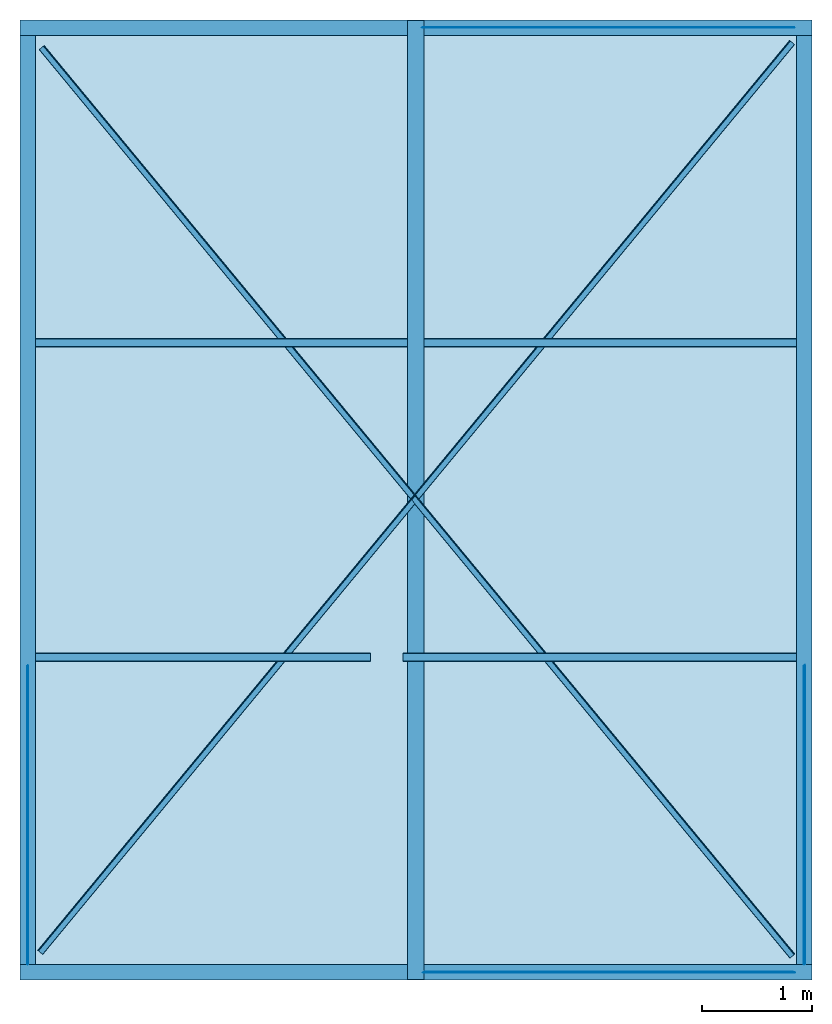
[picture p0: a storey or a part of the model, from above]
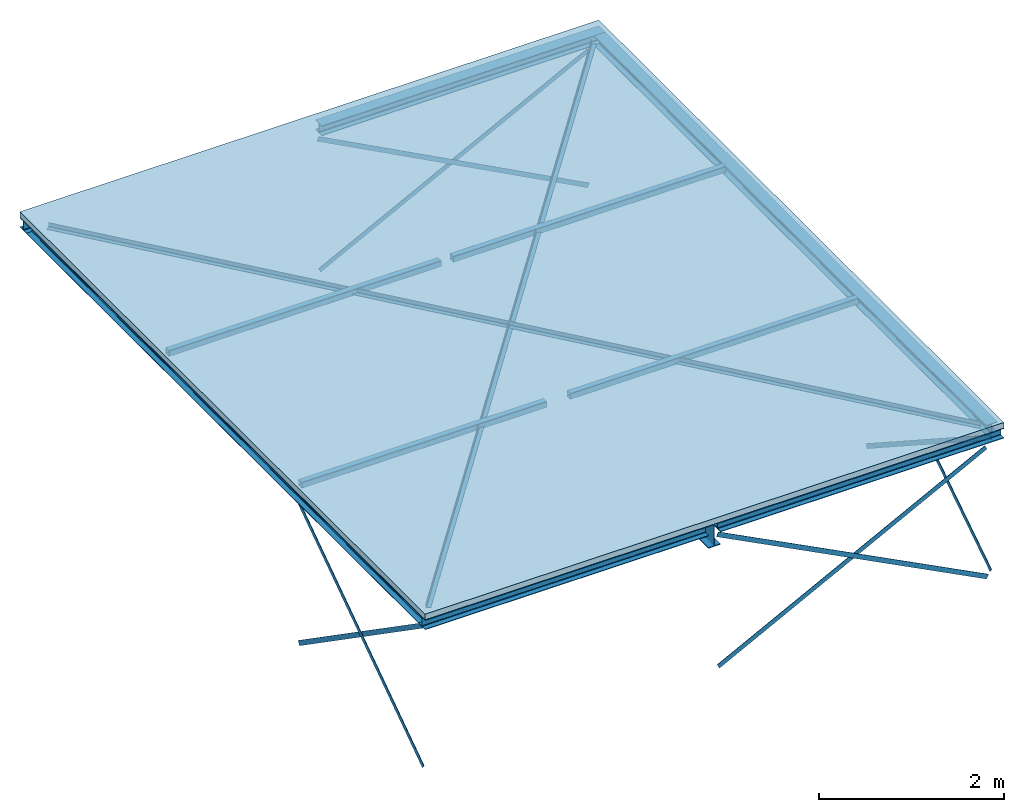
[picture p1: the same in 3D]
Properties of the parts of a building model (IFC2X3), part 1 of 2

# File
Description: ViewDefinition [CoordinationView_V2.0]
File name: 2021082
Time: 2022-08-02T08:48:02
Written by: The EXPRESS Data Manager Version 5.02.0100.07 : 28 Aug 2013
Made in: 22.0.2.392 - Exporter 22.0.2.392 - Alternate UI 22.0.2.392
Comment: STEP Physical File produced by: The EXPRESS Data Manager Version 5.02.0100.07 : 28 Aug 2013 * Module: EDMstepFileFactory/EDMstandAlone * Creation date: Tue Aug 02 08:48:02 2022 * Host: R2PC02 * Database: C:\Users\HANSVA~1\AppData\Local\Temp\1c85909f-41f3-4abc-839f-18ef85b8f30f\689eabe4-1559-4020-89f1-15476b5d3bc4\ifc * Database version: 5507 * Database creation date: Tue Aug 02 08:47:47 2022 * Schema: IFC2X3 * Model: DataRepository.ifc * Model creation date: Tue Aug 02 08:47:47 2022 * Header model: DataRepository.ifc_HeaderModel * Header model creation date: Tue Aug 02 08:47:47 2022 * EDMuser: sdai-user * EDMgroup: sdai-group * License ID and type: 5605 : Permanent license. Expiry date: * EDMstepFileFactory options: 020000

# IfcProject, 2021082
LongName: IKC Woensdrecht; Phase: Project Status

# IfcSite, Default
RefLatitude: 52, 22, 58, 797912; RefLongitude: 4, 54, 57, 599601; RefElevation: 0 mm
Pset_ProductRequirements - Category: Project Information

# IfcBuilding
Pset_BuildingCommon - NumberOfStoreys: 9
Pset_ProductRequirements - Category: Project Information

# IfcBuildingStorey: Level:A_hoogte_3.5mm (9)
Pset_ProductRequirements - Category: Levels
Name | LongName | Elevation (mm) | Pset_AirSideSystemInformation, Name = Pset_ProductRequirements, Name
-01 kelder | -01 kelder | -3500 | P.P.N
-00 fundatie | -00 fundatie | -1085 | -00 fundatie
00 begane grond | 00 begane grond | -2.70717e-13 | 00 begane grond
01 eerste verdieping | 01 eerste verdieping | 3500 | 01 eerste verdieping
02 tweede verdieping | 02 tweede verdieping | 7000 | 02 tweede verdieping
03 derde verdieping | 03 derde verdieping | 10500 | 03 derde verdieping
04 vierde verdieping | 04 vierde verdieping | 14000 | 04 vierde verdieping
05 vijfde verdieping | 05 vijfde verdieping | 17500 | 05 vijfde verdieping
06 zesde verdieping | 06 zesde verdieping | 21000 | 06 zesde verdieping

# IfcBeam: BERSnl_28_SF_LIB_balk hea -SH_gen_ISR:balk gen hea140 (7)
Type - PredefinedType: BEAM
Type - Pset_BeamCommon - IsExternal: no; LoadBearing: yes
Type - Pset_ProductRequirements - Category: Structural Framing
Type - Pset_ReinforcementBarPitchOfBeam - Description: HEA140
Classification: 28.10 hoofddraagconstructies; kolommen en liggers, algemeen (verzamelniveau) (Uniformat); Material: 00_Staal_generiek
Pset_BeamCommon - Slope: 0 deg; IsExternal: yes; Reference: balk gen hea140
Pset_PrecastConcreteElementGeneral - ElementWeight: 0 kg
Pset_QuantityTakeOff - Reference: balk gen hea140
Pset_ReinforcementBarPitchOfBeam - Reference: balk gen hea140
Name (BERSnl_28_SF_LIB_balk hea -SH_gen_ISR:balk gen hea140:...) | In | Span (mm)
849789 | 03 derde verdieping | 1500
851261 | 03 derde verdieping | 1000
851611 | 03 derde verdieping | 1500
852184 | 03 derde verdieping | 1920
855632 | 03 derde verdieping | 1500
855634 | 03 derde verdieping | 1500
966051 | 01 eerste verdieping | 3600

# IfcBeam: BERSnl_28_SF_LIB_balk hea -SH_gen_ISR:balk gen hea160 (9)
In: 01 eerste verdieping
Type - PredefinedType: BEAM
Type - Pset_BeamCommon - IsExternal: no; LoadBearing: yes
Type - Pset_ProductRequirements - Category: Structural Framing
Type - Pset_ReinforcementBarPitchOfBeam - Description: HEA160
Classification: 28.10 hoofddraagconstructies; kolommen en liggers, algemeen (verzamelniveau) (Uniformat); Material: 00_Staal_generiek
Pset_BeamCommon - IsExternal: yes; Reference: balk gen hea160
Pset_PrecastConcreteElementGeneral - ElementWeight: 0 kg
Pset_QuantityTakeOff - Reference: balk gen hea160
Pset_ReinforcementBarPitchOfBeam - Reference: balk gen hea160
Name (BERSnl_28_SF_LIB_balk hea -SH_gen_ISR:balk gen hea160:...) | Slope (deg) | Span (mm)
949146 | 0 | 2500
949247 | 0 | 2500
949938 | 0.963939 | 8916.3
953803 | 0 | 2500
953818 | 0 | 2500
954060 | 0 | 2500
954073 | 0 | 2500
959555 | 0 | 2500
959983 | 0 | 2500

# IfcBeam: BERSnl_28_SF_LIB_balk hea -SH_gen_ISR:balk gen hea180 (2)
In: 01 eerste verdieping
Type - PredefinedType: BEAM
Type - Pset_BeamCommon - IsExternal: no; LoadBearing: yes
Type - Pset_ProductRequirements - Category: Structural Framing
Type - Pset_ReinforcementBarPitchOfBeam - Description: HEA180
Classification: 28.10 hoofddraagconstructies; kolommen en liggers, algemeen (verzamelniveau) (Uniformat); Material: 00_Staal_generiek
Pset_BeamCommon - Slope: 0 deg; IsExternal: yes; Reference: balk gen hea180; Span: 1500 mm
Pset_PrecastConcreteElementGeneral - ElementWeight: 0 kg
Pset_QuantityTakeOff - Reference: balk gen hea180
Pset_ReinforcementBarPitchOfBeam - Reference: balk gen hea180
Name (BERSnl_28_SF_LIB_balk hea -SH_gen_ISR:balk gen hea180:...)
1052827
1053251

# IfcBeam: BERSnl_28_SF_LIB_balk hea -SH_gen_ISR:balk gen hea300 (2)
In: 02 tweede verdieping
Type - PredefinedType: BEAM
Type - Pset_BeamCommon - IsExternal: no; LoadBearing: yes; FireRating: 90
Type - Pset_ConcreteElementGeneral - FireRating: 90
Type - Pset_ProductRequirements - Category: Structural Framing
Type - Pset_ReinforcementBarPitchOfBeam - Description: HEA300
Classification: 28.10 hoofddraagconstructies; kolommen en liggers, algemeen (verzamelniveau) (Uniformat); Material: 00_Staal_generiek
Pset_BeamCommon - Slope: 0 deg; IsExternal: yes; Reference: balk gen hea300
Pset_PrecastConcreteElementGeneral - ElementWeight: 0 kg
Pset_QuantityTakeOff - Reference: balk gen hea300
Pset_ReinforcementBarPitchOfBeam - Reference: balk gen hea300
Name (BERSnl_28_SF_LIB_balk hea -SH_gen_ISR:balk gen hea300:...) | Span (mm)
876535 | 3420
1185423 | 6369.5

# IfcBeam: BERSnl_28_SF_LIB_balk hea -SH_gen_ISR:balk gen hea360, BERSnl_28_SF_LIB_balk hea -SH_gen_ISR:balk gen hea360:864340
In: 02 tweede verdieping
Type - PredefinedType: BEAM
Type - Pset_BeamCommon - IsExternal: no; LoadBearing: yes; FireRating: 90
Type - Pset_ConcreteElementGeneral - FireRating: 90
Type - Pset_ProductRequirements - Category: Structural Framing
Type - Pset_ReinforcementBarPitchOfBeam - Description: HEA360
Classification: 28.10 hoofddraagconstructies; kolommen en liggers, algemeen (verzamelniveau) (Uniformat); Material: 00_Staal_generiek
Pset_BeamCommon - Slope: 0 deg; IsExternal: yes; Reference: balk gen hea360; Span: 2800 mm
Pset_PrecastConcreteElementGeneral - ElementWeight: 0 kg
Pset_QuantityTakeOff - Reference: balk gen hea360
Pset_ReinforcementBarPitchOfBeam - Reference: balk gen hea360

# IfcBeam: BERSnl_28_SF_LIB_balk heb_gen_ISR:balk gen heb200 (5)
Type - PredefinedType: BEAM
Type - Pset_BeamCommon - IsExternal: no; LoadBearing: yes
Type - Pset_ProductRequirements - Category: Structural Framing
Type - Pset_ReinforcementBarPitchOfBeam - Description: HEB200
Classification: 28.10 hoofddraagconstructies; kolommen en liggers, algemeen (verzamelniveau) (Uniformat); Material: 00_Staal_generiek
Pset_BeamCommon - Slope: 0 deg; IsExternal: yes; Reference: balk gen heb200
Pset_PrecastConcreteElementGeneral - ElementWeight: 0 kg
Pset_QuantityTakeOff - Reference: balk gen heb200
Pset_ReinforcementBarPitchOfBeam - Reference: balk gen heb200
Name (BERSnl_28_SF_LIB_balk heb_gen_ISR:balk gen heb200:...) | In | Span (mm)
688986 | 01 eerste verdieping | 1500
692236 | 01 eerste verdieping | 3334
698934 | 01 eerste verdieping | 1500
783342 | 01 eerste verdieping | 880
821963 | 02 tweede verdieping | 2500

# IfcBeam: BERSnl_28_SF_LIB_balk heb_gen_ISR:balk gen heb240 (2)
In: 01 eerste verdieping
Type - PredefinedType: BEAM
Type - Pset_BeamCommon - IsExternal: no; LoadBearing: yes
Type - Pset_ProductRequirements - Category: Structural Framing
Type - Pset_ReinforcementBarPitchOfBeam - Description: HEB240
Classification: 28.10 hoofddraagconstructies; kolommen en liggers, algemeen (verzamelniveau) (Uniformat); Material: 00_Staal_generiek
Pset_BeamCommon - Slope: 0 deg; IsExternal: yes; Reference: balk gen heb240
Pset_PrecastConcreteElementGeneral - ElementWeight: 0 kg
Pset_QuantityTakeOff - Reference: balk gen heb240
Pset_ReinforcementBarPitchOfBeam - Reference: balk gen heb240
Name (BERSnl_28_SF_LIB_balk heb_gen_ISR:balk gen heb240:...) | Span (mm)
794454 | 680
803762 | 700

# IfcBeam: BERSnl_28_SF_LIB_balk heb_gen_ISR:balk gen heb300 (4)
In: 01 eerste verdieping
Type - PredefinedType: BEAM
Type - Pset_BeamCommon - IsExternal: no; LoadBearing: yes; FireRating: 90
Type - Pset_ConcreteElementGeneral - FireRating: 90
Type - Pset_ProductRequirements - Category: Structural Framing
Type - Pset_ReinforcementBarPitchOfBeam - Description: HEB300
Classification: 28.10 hoofddraagconstructies; kolommen en liggers, algemeen (verzamelniveau) (Uniformat); Material: 00_Staal_generiek
Pset_BeamCommon - Slope: 0 deg; IsExternal: yes; Reference: balk gen heb300
Pset_PrecastConcreteElementGeneral - ElementWeight: 0 kg
Pset_QuantityTakeOff - Reference: balk gen heb300
Pset_ReinforcementBarPitchOfBeam - Reference: balk gen heb300
Name (BERSnl_28_SF_LIB_balk heb_gen_ISR:balk gen heb300:...) | Span (mm)
688498 | 2080
701449 | 1723
703433 | 860
742120 | 3560

# IfcBeam: BERSnl_28_SF_LIB_balk heb_gen_ISR:balk gen heb320, BERSnl_28_SF_LIB_balk heb_gen_ISR:balk gen heb320:831326
In: 02 tweede verdieping
Type - PredefinedType: BEAM
Type - Pset_BeamCommon - IsExternal: no; LoadBearing: yes; FireRating: 90
Type - Pset_ConcreteElementGeneral - FireRating: 90
Type - Pset_ProductRequirements - Category: Structural Framing
Type - Pset_ReinforcementBarPitchOfBeam - Description: HEB320
Classification: 28.10 hoofddraagconstructies; kolommen en liggers, algemeen (verzamelniveau) (Uniformat); Material: 00_Staal_generiek
Pset_BeamCommon - Slope: 0 deg; IsExternal: yes; Reference: balk gen heb320; Span: 1960 mm
Pset_PrecastConcreteElementGeneral - ElementWeight: 0 kg
Pset_QuantityTakeOff - Reference: balk gen heb320
Pset_ReinforcementBarPitchOfBeam - Reference: balk gen heb320

# IfcBeam: BERSnl_28_SF_LIB_balk heb_gen_ISR:balk gen heb400 (3)
In: 01 eerste verdieping
Type - PredefinedType: BEAM
Type - Pset_BeamCommon - IsExternal: no; LoadBearing: yes; FireRating: 90
Type - Pset_ConcreteElementGeneral - FireRating: 90
Type - Pset_ProductRequirements - Category: Structural Framing
Type - Pset_ReinforcementBarPitchOfBeam - Description: HEB400
Classification: 28.10 S355 (Uniformat); Material: 00_Staal_generiek
Pset_BeamCommon - Slope: 0 deg; IsExternal: yes; Reference: balk gen heb400
Pset_PrecastConcreteElementGeneral - ElementWeight: 0 kg
Pset_QuantityTakeOff - Reference: balk gen heb400
Pset_ReinforcementBarPitchOfBeam - Reference: balk gen heb400
Name (BERSnl_28_SF_LIB_balk heb_gen_ISR:balk gen heb400:...) | Span (mm)
677856 | 1500
775191 | 2600
789859 | 2600

# IfcBeam: BERSnl_28_SF_LIB_balk heb_gen_ISR:balk gen heb450, BERSnl_28_SF_LIB_balk heb_gen_ISR:balk gen heb450:823352
In: 02 tweede verdieping
Type - PredefinedType: BEAM
Type - Pset_BeamCommon - IsExternal: no; LoadBearing: yes
Type - Pset_ProductRequirements - Category: Structural Framing
Type - Pset_ReinforcementBarPitchOfBeam - Description: HEB450
Classification: 28.10 hoofddraagconstructies; kolommen en liggers, algemeen (verzamelniveau) (Uniformat); Material: 00_Staal_generiek
Pset_BeamCommon - Slope: 0 deg; IsExternal: yes; Reference: balk gen heb450; Span: 1500 mm
Pset_PrecastConcreteElementGeneral - ElementWeight: 0 kg
Pset_QuantityTakeOff - Reference: balk gen heb450
Pset_ReinforcementBarPitchOfBeam - Reference: balk gen heb450

# IfcBeam: BERSnl_28_SF_LIB_balk hoeklijn ongelijk_gen_ISR:balk gen l150x100x10 (72)
Type - PredefinedType: BEAM
Type - Pset_BeamCommon - IsExternal: no; LoadBearing: yes
Type - Pset_ProductRequirements - Category: Structural Framing
Type - Pset_ReinforcementBarPitchOfBeam - Description: L150X100X10
Classification: 28.10 hoofddraagconstructies; kolommen en liggers, algemeen (verzamelniveau) (Uniformat); Material: 00_Staal_generiek
Pset_BeamCommon - Slope: 0 deg; IsExternal: yes; Reference: balk gen l150x100x10
Pset_PrecastConcreteElementGeneral - ElementWeight: 0 kg
Pset_QuantityTakeOff - Reference: balk gen l150x100x10
Pset_ReinforcementBarPitchOfBeam - Reference: balk gen l150x100x10
Name (BERSnl_28_SF_LIB_balk hoeklijn ongelijk_gen_ISR:balk gen l150x100x10:...) | In | Span (mm)
660354 | 01 eerste verdieping | 1500
670744 | 01 eerste verdieping | 1500
671900 | 01 eerste verdieping | 1500
672489 | 01 eerste verdieping | 1500
673755 | 01 eerste verdieping | 1500
685783 | 01 eerste verdieping | 1500
685802 | 01 eerste verdieping | 1500
691057 | 01 eerste verdieping | 1000
694901 | 01 eerste verdieping | 1000
710700 | 01 eerste verdieping | 1500
719581 | 01 eerste verdieping | 1620
721606 | 01 eerste verdieping | 1620
722290 | 01 eerste verdieping | 1620
727999 | 01 eerste verdieping | 1620
729041 | 01 eerste verdieping | 1620
729063 | 01 eerste verdieping | 1620
729091 | 01 eerste verdieping | 1620
773337 | 01 eerste verdieping | 1540
773974 | 01 eerste verdieping | 1540
774482 | 01 eerste verdieping | 1739.3
774847 | 01 eerste verdieping | 1539.9
788580 | 01 eerste verdieping | 1700
789357 | 01 eerste verdieping | 1700
807034 | 01 eerste verdieping | 1700
807650 | 01 eerste verdieping | 1700
809742 | 01 eerste verdieping | 1700
809744 | 01 eerste verdieping | 1700
811694 | 01 eerste verdieping | 1400
813131 | 01 eerste verdieping | 1400
813154 | 01 eerste verdieping | 1400
813417 | 01 eerste verdieping | 1400
825874 | 02 tweede verdieping | 1460
827069 | 02 tweede verdieping | 1460
829571 | 02 tweede verdieping | 860
830294 | 02 tweede verdieping | 860
830373 | 02 tweede verdieping | 860
830394 | 02 tweede verdieping | 860
830713 | 02 tweede verdieping | 860
830759 | 02 tweede verdieping | 860
830781 | 02 tweede verdieping | 860
833316 | 02 tweede verdieping | 1460
833341 | 02 tweede verdieping | 1460
833370 | 02 tweede verdieping | 1460
837409 | 02 tweede verdieping | 1460
837467 | 02 tweede verdieping | 1460
863016 | 02 tweede verdieping | 1100
867993 | 02 tweede verdieping | 1100
868016 | 02 tweede verdieping | 1100
868037 | 02 tweede verdieping | 1100
871078 | 02 tweede verdieping | 1100
871134 | 02 tweede verdieping | 1100
871151 | 02 tweede verdieping | 1100
871176 | 02 tweede verdieping | 1100
881732 | 02 tweede verdieping | 1100
887412 | 02 tweede verdieping | 1320
896766 | 02 tweede verdieping | 760
898825 | 02 tweede verdieping | 920
899896 | 02 tweede verdieping | 920
907095 | 02 tweede verdieping | 920
907109 | 02 tweede verdieping | 920
916072 | 02 tweede verdieping | 920
916085 | 02 tweede verdieping | 920
1140469 | 01 eerste verdieping | 720
1143199 | 01 eerste verdieping | 720
1215608 | 01 eerste verdieping | 1500
1226239 | 01 eerste verdieping | 1500
1233577 | 02 tweede verdieping | 2600
1238871 | 01 eerste verdieping | 1739.3
1240635 | 02 tweede verdieping | 1320
1241881 | 02 tweede verdieping | 1320
1249829 | 01 eerste verdieping | 1400
1254640 | 02 tweede verdieping | 1400

# IfcBeam: BERSnl_28_SF_LIB_balk hoeklijn ongelijk_gen_ISR:balk gen l200x100x10 (2)
In: 02 tweede verdieping
Type - PredefinedType: BEAM
Type - Pset_BeamCommon - IsExternal: no; LoadBearing: yes
Type - Pset_ProductRequirements - Category: Structural Framing
Type - Pset_ReinforcementBarPitchOfBeam - Description: L200X100X10
Classification: 28.10 hoofddraagconstructies; kolommen en liggers, algemeen (verzamelniveau) (Uniformat); Material: 00_Staal_generiek
Pset_BeamCommon - Slope: 0 deg; IsExternal: yes; Reference: balk gen l200x100x10
Pset_PrecastConcreteElementGeneral - ElementWeight: 0 kg
Pset_QuantityTakeOff - Reference: balk gen l200x100x10
Pset_ReinforcementBarPitchOfBeam - Reference: balk gen l200x100x10
Name (BERSnl_28_SF_LIB_balk hoeklijn ongelijk_gen_ISR:balk gen l200x100x10:...) | Span (mm)
884309 | 1280.7
884511 | 1011.8

# IfcBeam: BERSnl_28_SF_LIB_balk hoeklijn_gen_ISR:balk gen l120x10, BERSnl_28_SF_LIB_balk hoeklijn_gen_ISR:balk gen l120x10:1335914
In: 02 tweede verdieping
Type - PredefinedType: BEAM
Type - Pset_BeamCommon - IsExternal: no; LoadBearing: yes
Type - Pset_ProductRequirements - Category: Structural Framing
Type - Pset_ReinforcementBarPitchOfBeam - Description: L120X10
Classification: 28.10 hoofddraagconstructies; kolommen en liggers, algemeen (verzamelniveau) (Uniformat); Material: 00_Staal_generiek
Pset_BeamCommon - IsExternal: yes; Reference: balk gen l120x10; Span: 1800.1 mm; Slope: 0.963973 deg
Pset_PrecastConcreteElementGeneral - ElementWeight: 0 kg
Pset_QuantityTakeOff - Reference: balk gen l120x10
Pset_ReinforcementBarPitchOfBeam - Reference: balk gen l120x10

# IfcBeam: BERSnl_28_SF_LIB_balk hoeklijn_gen_ISR:balk gen l60x6 (2)
In: 03 derde verdieping
Type - PredefinedType: BEAM
Type - Pset_BeamCommon - IsExternal: no; LoadBearing: yes
Type - Pset_ProductRequirements - Category: Structural Framing
Type - Pset_ReinforcementBarPitchOfBeam - Description: L60X6
Classification: 28.10 hoofddraagconstructies; kolommen en liggers, algemeen (verzamelniveau) (Uniformat); Material: 00_Staal_generiek
Pset_BeamCommon - Slope: 0 deg; IsExternal: yes; Reference: balk gen l60x6
Pset_PrecastConcreteElementGeneral - ElementWeight: 0 kg
Pset_QuantityTakeOff - Reference: balk gen l60x6
Pset_ReinforcementBarPitchOfBeam - Reference: balk gen l60x6
Name (BERSnl_28_SF_LIB_balk hoeklijn_gen_ISR:balk gen l60x6:...) | Span (mm)
860354 | 10760
860822 | 10820

# IfcBeam: BERSnl_28_SF_LIB_balk hoeklijn_gen_ISR:balk gen l80x8 (8)
In: 01 eerste verdieping
Type - PredefinedType: BEAM
Type - Pset_BeamCommon - IsExternal: no; LoadBearing: yes
Type - Pset_ProductRequirements - Category: Structural Framing
Type - Pset_ReinforcementBarPitchOfBeam - Description: L80X8
Classification: 28.10 hoofddraagconstructies; kolommen en liggers, algemeen (verzamelniveau) (Uniformat); Material: 00_Staal_generiek
Pset_BeamCommon - IsExternal: yes; Reference: balk gen l80x8
Pset_PrecastConcreteElementGeneral - ElementWeight: 0 kg
Pset_QuantityTakeOff - Reference: balk gen l80x8
Pset_ReinforcementBarPitchOfBeam - Reference: balk gen l80x8
Name (BERSnl_28_SF_LIB_balk hoeklijn_gen_ISR:balk gen l80x8:...) | Span (mm) | Slope (deg)
966963 | 4460.1 | 0.462472
968332 | 5680 | 0.151309
968643 | 4460.1 | 0.462472
968645 | 5674.8 | 0.252414
968659 | 4460 | 0
968661 | 5680 | 0
968664 | 4460 | 0
968666 | 5680 | 0

# IfcBeam: BERSnl_28_SF_LIB_balk ipe -SH_gen_ISR:balk gen ipe220, BERSnl_28_SF_LIB_balk ipe -SH_gen_ISR:balk gen ipe220:1340080
In: 01 eerste verdieping
Type - PredefinedType: BEAM
Type - Pset_BeamCommon - IsExternal: no; LoadBearing: yes
Type - Pset_ProductRequirements - Category: Structural Framing
Type - Pset_ReinforcementBarPitchOfBeam - Description: IPE220
Classification: 28.10 hoofddraagconstructies; kolommen en liggers, algemeen (verzamelniveau) (Uniformat); Material: 00_Staal_generiek
Pset_BeamCommon - Slope: 0 deg; IsExternal: yes; Reference: balk gen ipe220; Span: 1500 mm
Pset_PrecastConcreteElementGeneral - ElementWeight: 0 kg
Pset_QuantityTakeOff - Reference: balk gen ipe220
Pset_ReinforcementBarPitchOfBeam - Reference: balk gen ipe220

# IfcBeam: BERSnl_28_SF_LIB_balk ipe -SH_gen_ISR:balk gen ipe300, BERSnl_28_SF_LIB_balk ipe -SH_gen_ISR:balk gen ipe300:847441
In: 03 derde verdieping
Type - PredefinedType: BEAM
Type - Pset_BeamCommon - IsExternal: no; LoadBearing: yes
Type - Pset_ProductRequirements - Category: Structural Framing
Type - Pset_ReinforcementBarPitchOfBeam - Description: IPE300
Classification: 28.10 hoofddraagconstructies; kolommen en liggers, algemeen (verzamelniveau) (Uniformat); Material: 00_Staal_generiek
Pset_BeamCommon - Slope: 0 deg; IsExternal: yes; Reference: balk gen ipe300; Span: 1500 mm
Pset_PrecastConcreteElementGeneral - ElementWeight: 0 kg
Pset_QuantityTakeOff - Reference: balk gen ipe300
Pset_ReinforcementBarPitchOfBeam - Reference: balk gen ipe300

# IfcBeam: BERSnl_28_SF_LIB_balk ipe -SH_gen_ISR:balk gen ipe500 (3)
In: 01 eerste verdieping
Type - PredefinedType: BEAM
Type - Pset_BeamCommon - IsExternal: no; LoadBearing: yes
Type - Pset_ProductRequirements - Category: Structural Framing
Type - Pset_ReinforcementBarPitchOfBeam - Description: IPE500
Classification: 28.10 hoofddraagconstructies; kolommen en liggers, algemeen (verzamelniveau) (Uniformat); Material: 00_Staal_generiek
Pset_BeamCommon - IsExternal: yes; Reference: balk gen ipe500; Span: 8916.3 mm; Slope: 0.963939 deg
Pset_PrecastConcreteElementGeneral - ElementWeight: 0 kg
Pset_QuantityTakeOff - Reference: balk gen ipe500
Pset_ReinforcementBarPitchOfBeam - Reference: balk gen ipe500
Name (BERSnl_28_SF_LIB_balk ipe -SH_gen_ISR:balk gen ipe500:...)
947628
954699
954815

# IfcBeam: BERSnl_28_SF_LIB_balk koker ongelijk_gen_ISR:balk gen k100x60x5, BERSnl_28_SF_LIB_balk koker ongelijk_gen_ISR:balk gen k100x60x5:1294141
In: 01 eerste verdieping
Type - PredefinedType: BEAM
Type - Pset_BeamCommon - IsExternal: no; LoadBearing: yes
Type - Pset_ProductRequirements - Category: Structural Framing
Type - Pset_ReinforcementBarPitchOfBeam - Description: K100x60x5
Classification: 28.10 hoofddraagconstructies; kolommen en liggers, algemeen (verzamelniveau) (Uniformat); Material: h2_staal S235
Pset_BeamCommon - Slope: 0 deg; IsExternal: yes; Reference: balk gen k100x60x5; Span: 1500 mm
Pset_PrecastConcreteElementGeneral - ElementWeight: 0 kg
Pset_QuantityTakeOff - Reference: balk gen k100x60x5
Pset_ReinforcementBarPitchOfBeam - Reference: balk gen k100x60x5

# IfcBeam: BERSnl_28_SF_LIB_balk koker ongelijk_gen_ISR:balk gen k200x100x10, BERSnl_28_SF_LIB_balk koker ongelijk_gen_ISR:balk gen k200x100x10:1211957
In: -00 fundatie
Type - PredefinedType: BEAM
Type - Pset_BeamCommon - IsExternal: no; LoadBearing: yes
Type - Pset_ProductRequirements - Category: Structural Framing
Type - Pset_ReinforcementBarPitchOfBeam - Description: K200x100x10
Classification: 28.10 hoofddraagconstructies; kolommen en liggers, algemeen (verzamelniveau) (Uniformat); Material: h2_staal S235
Pset_BeamCommon - Slope: 0 deg; IsExternal: yes; Reference: balk gen k200x100x10; Span: 1500 mm
Pset_PrecastConcreteElementGeneral - ElementWeight: 0 kg
Pset_QuantityTakeOff - Reference: balk gen k200x100x10
Pset_ReinforcementBarPitchOfBeam - Reference: balk gen k200x100x10

# IfcBeam: BERSnl_28_SF_LIB_balk koker vierkant_gen_ISR:balk gen k80x80x4 (7)
Type - PredefinedType: BEAM
Type - Pset_BeamCommon - IsExternal: no; LoadBearing: yes
Type - Pset_ProductRequirements - Category: Structural Framing
Type - Pset_ReinforcementBarPitchOfBeam - Description: K80x80x4
Classification: 28.10 hoofddraagconstructies; kolommen en liggers, algemeen (verzamelniveau) (Uniformat)
Pset_BeamCommon - Slope: 0 deg; IsExternal: yes; Reference: balk gen k80x80x4
Pset_PrecastConcreteElementGeneral - ElementWeight: 0 kg
Pset_QuantityTakeOff - Reference: balk gen k80x80x4
Pset_ReinforcementBarPitchOfBeam - Reference: balk gen k80x80x4
Name (BERSnl_28_SF_LIB_balk koker vierkant_gen_ISR:balk gen k80x80x4:...) | In | Material | Span (mm)
852722 | 03 derde verdieping | h2_staal S235 | 1527.8
854635 | 03 derde verdieping | h2_staal S235 | 1500
855232 | 03 derde verdieping | h2_staal S235 | 1500
855234 | 03 derde verdieping | h2_staal S235 | 1500
964993 | 01 eerste verdieping | 00_Staal_generiek | 5397.4
966303 | 01 eerste verdieping | 00_Staal_generiek | 5397.4
966322 | 01 eerste verdieping | 00_Staal_generiek | 5397.4

# IfcBeam: BERSnl_28_SF_LIB_balk sfb_gen_ISR:balk gen heb200 400x15 (14)
Type - PredefinedType: T_BEAM; Classification: 28.10 S355 (Uniformat); Material: <Unnamed>, 00_Staal_generiek
Type - Pset_BeamCommon - IsExternal: no; LoadBearing: yes; FireRating: 90
Type - Pset_ConcreteElementGeneral - FireRating: 90
Type - Pset_ProductRequirements - Category: Structural Framing
Type - Pset_ReinforcementBarPitchOfBeam - Description: SFB-HEB200 400x15
Pset_BeamCommon - Slope: 0 deg; IsExternal: yes; Reference: balk gen heb200 400x15
Pset_PrecastConcreteElementGeneral - ElementWeight: 0 kg
Pset_QuantityTakeOff - Reference: balk gen heb200 400x15
Pset_ReinforcementBarPitchOfBeam - Reference: balk gen heb200 400x15
Name (BERSnl_28_SF_LIB_balk sfb_gen_ISR:balk gen heb200 400x15:...) | In | Span (mm)
676763 | 01 eerste verdieping | 2680
682230 | 01 eerste verdieping | 2680
699292 | 01 eerste verdieping | 1060
733528 | 01 eerste verdieping | 2160
776541 | 01 eerste verdieping | 2700
781277 | 01 eerste verdieping | 4320
789863 | 01 eerste verdieping | 2700
789867 | 01 eerste verdieping | 4320
834627 | 02 tweede verdieping | 5972.37
876239 | 02 tweede verdieping | 1780
890053 | 02 tweede verdieping | 11790
901041 | 02 tweede verdieping | 3480
1292684 | 01 eerste verdieping | 1800
1294810 | 02 tweede verdieping | 1560

# IfcBeam: BERSnl_28_SF_LIB_balk sfb_gen_ISR:balk gen heb200 400x15 (2)
Type - PredefinedType: T_BEAM; Classification: 28.10 S355 (Uniformat); Material: h2_staal
Type - Pset_BeamCommon - IsExternal: no; LoadBearing: yes; FireRating: 90
Type - Pset_ConcreteElementGeneral - FireRating: 90
Type - Pset_ProductRequirements - Category: Structural Framing
Type - Pset_ReinforcementBarPitchOfBeam - Description: SFB-HEB200 400x15
Pset_BeamCommon - Slope: 0 deg; IsExternal: yes; Reference: balk gen heb200 400x15; Span: 1500 mm
Pset_PrecastConcreteElementGeneral - ElementWeight: 0 kg
Pset_QuantityTakeOff - Reference: balk gen heb200 400x15
Pset_ReinforcementBarPitchOfBeam - Reference: balk gen heb200 400x15
Name (BERSnl_28_SF_LIB_balk sfb_gen_ISR:balk gen heb200 400x15:...) | In
655065 | 01 eerste verdieping
819993 | 02 tweede verdieping

# IfcBeam: BERSnl_28_SF_LIB_balk strip_gen_ISR:balk strip gen 300x15 (3)
Type - PredefinedType: USERDEFINED
Type - Pset_BeamCommon - IsExternal: no; LoadBearing: yes
Type - Pset_ProductRequirements - Category: Structural Framing
Type - Pset_ReinforcementBarPitchOfBeam - Description: 300x15
Classification: 28.10 (S355) (Uniformat)
Pset_BeamCommon - Slope: 0 deg; IsExternal: yes; Reference: balk strip gen 300x15
Pset_PrecastConcreteElementGeneral - ElementWeight: 0 kg
Pset_QuantityTakeOff - Reference: balk strip gen 300x15
Pset_ReinforcementBarPitchOfBeam - Reference: balk strip gen 300x15
Name (BERSnl_28_SF_LIB_balk strip_gen_ISR:balk strip gen 300x15:...) | In | Material | Span (mm)
692446 | 01 eerste verdieping | h2_staal | 1500
783446 | 01 eerste verdieping | 00_Staal_generiek | 729.779
821911 | 02 tweede verdieping | 00_Staal_generiek | 1500

# IfcBeam: BERSnl_28_SF_LIB_balk strip_gen_ISR:balk strip gen 400x15, BERSnl_28_SF_LIB_balk strip_gen_ISR:balk strip gen 400x15:701954
In: 01 eerste verdieping
Type - PredefinedType: USERDEFINED
Type - Pset_BeamCommon - IsExternal: no; LoadBearing: yes
Type - Pset_ProductRequirements - Category: Structural Framing
Type - Pset_ReinforcementBarPitchOfBeam - Description: 300x15
Classification: 28.10 hoofddraagconstructies; kolommen en liggers, algemeen (verzamelniveau) (Uniformat); Material: h2_staal
Pset_BeamCommon - Slope: 0 deg; IsExternal: yes; Reference: balk strip gen 400x15; Span: 1500 mm
Pset_PrecastConcreteElementGeneral - ElementWeight: 0 kg
Pset_QuantityTakeOff - Reference: balk strip gen 400x15
Pset_ReinforcementBarPitchOfBeam - Reference: balk strip gen 400x15

# IfcBeam: BERSnl_28_SF_LIB_balk strip_gen_ISR:balk strip gen 60x6 (14)
Type - PredefinedType: USERDEFINED
Type - Pset_BeamCommon - IsExternal: no; LoadBearing: yes
Type - Pset_ProductRequirements - Category: Structural Framing
Type - Pset_ReinforcementBarPitchOfBeam - Description: 60x6
Classification: 28.10 hoofddraagconstructies; kolommen en liggers, algemeen (verzamelniveau) (Uniformat); Material: 00_Staal_generiek
Pset_BeamCommon - IsExternal: yes; Reference: balk strip gen 60x6
Pset_PrecastConcreteElementGeneral - ElementWeight: 0 kg
Pset_QuantityTakeOff - Reference: balk strip gen 60x6
Pset_ReinforcementBarPitchOfBeam - Reference: balk strip gen 60x6
Name (BERSnl_28_SF_LIB_balk strip_gen_ISR:balk strip gen 60x6:...) | In | Span (mm) | Slope (deg)
856180 | 03 derde verdieping | 3720 | 27.2783
857208 | 03 derde verdieping | 3620 | 28
857429 | 03 derde verdieping | 3720 | 27.2783
857431 | 03 derde verdieping | 3720 | 27.2783
857751 | 03 derde verdieping | 3160 | 33
858414 | 03 derde verdieping | 3160 | 33
858674 | 03 derde verdieping | 3220 | 34.5638
858676 | 03 derde verdieping | 3220 | 34.7421
960406 | 01 eerste verdieping | 8475 | 47
961377 | 01 eerste verdieping | 8475 | 47
961908 | 01 eerste verdieping | 7660 | 52.6448
962792 | 01 eerste verdieping | 7705 | 53
963102 | 01 eerste verdieping | 7760 | 53.4769
963104 | 01 eerste verdieping | 7820 | 53.6092

# IfcBeam: BERSnl_28_SF_LIB_balk unp_gen_ISR:balk_gen_UNP140 (23)
Type - PredefinedType: BEAM
Type - Pset_BeamCommon - IsExternal: no; LoadBearing: yes
Type - Pset_ProductRequirements - Category: Structural Framing
Type - Pset_ReinforcementBarPitchOfBeam - Description: UNP140
Classification: 28.10 hoofddraagconstructies; kolommen en liggers, algemeen (verzamelniveau) (Uniformat); Material: 00_Staal_generiek
Pset_BeamCommon - Slope: 0 deg; IsExternal: yes; Reference: balk_gen_UNP140
Pset_PrecastConcreteElementGeneral - ElementWeight: 0 kg
Pset_QuantityTakeOff - Reference: balk_gen_UNP140
Pset_ReinforcementBarPitchOfBeam - Reference: balk_gen_UNP140
Name (BERSnl_28_SF_LIB_balk unp_gen_ISR:balk_gen_UNP140:...) | In | Span (mm)
938462 | -00 fundatie | 1500
946217 | -00 fundatie | 3500
946690 | -00 fundatie | 3500
946711 | -00 fundatie | 3500
947005 | -00 fundatie | 3500
958085 | 01 eerste verdieping | 860
1058794 | 00 begane grond | 1500
1059038 | 00 begane grond | 1500
1059209 | 00 begane grond | 1500
1059387 | 00 begane grond | 1500
1062959 | 00 begane grond | 1500
1063926 | 00 begane grond | 1500
1069548 | -00 fundatie | 3500
1069708 | -00 fundatie | 3500
1069825 | -00 fundatie | 3500
1208265 | 00 begane grond | 1500
1210743 | 00 begane grond | 1500
1210928 | 00 begane grond | 1500
1257490 | 01 eerste verdieping | 3500
1258141 | 01 eerste verdieping | 3500
1258462 | 01 eerste verdieping | 1500
1258887 | 01 eerste verdieping | 1500
1272134 | 00 begane grond | 1500

# IfcBeam: BERSnl_28_SF_LIB_balk unp_gen_ISR:balk_gen_UNP180 (11)
Type - PredefinedType: BEAM
Type - Pset_BeamCommon - IsExternal: no; LoadBearing: yes
Type - Pset_ProductRequirements - Category: Structural Framing
Type - Pset_ReinforcementBarPitchOfBeam - Description: UNP180
Classification: 28.10 hoofddraagconstructies; kolommen en liggers, algemeen (verzamelniveau) (Uniformat); Material: 00_Staal_generiek
Pset_BeamCommon - Slope: 0 deg; IsExternal: yes; Reference: balk_gen_UNP180
Pset_PrecastConcreteElementGeneral - ElementWeight: 0 kg
Pset_QuantityTakeOff - Reference: balk_gen_UNP180
Pset_ReinforcementBarPitchOfBeam - Reference: balk_gen_UNP180
Name (BERSnl_28_SF_LIB_balk unp_gen_ISR:balk_gen_UNP180:...) | In | Span (mm)
1064074 | 00 begane grond | 1500
1204276 | 01 eerste verdieping | 1500
1204411 | 01 eerste verdieping | 1500
1204432 | 01 eerste verdieping | 1500
1205016 | 01 eerste verdieping | 3500
1205108 | 01 eerste verdieping | 3500
1205127 | 01 eerste verdieping | 3500
1205654 | 00 begane grond | 3500
1206285 | 01 eerste verdieping | 1500
1211931 | 00 begane grond | 1500
1267257 | 01 eerste verdieping | 1500

# IfcBeam: BERSnl_28_SF_LIB_balk vierkant beton_gen_ISR:balk vierkant 100x395 (39)
In: -00 fundatie
Type - PredefinedType: JOIST
Type - Pset_BeamCommon - IsExternal: no; LoadBearing: yes
Type - Pset_ProductRequirements - Category: Structural Framing
Type - Pset_ReinforcementBarPitchOfBeam - Description: balk 200x350
Classification: 28.10 hoofddraagconstructies; kolommen en liggers, algemeen (verzamelniveau) (Uniformat); Material: f2_beton ihwg
Pset_BeamCommon - IsExternal: yes; Reference: balk vierkant 100x395
Pset_PrecastConcreteElementGeneral - ElementWeight: 0 kg
Pset_QuantityTakeOff - Reference: balk vierkant 100x395
Pset_ReinforcementBarPitchOfBeam - Reference: balk vierkant 100x395
Name (BERSnl_28_SF_LIB_balk vierkant beton_gen_ISR:balk vierkant 100x395:...) | Slope (deg) | Span (mm)
1380300 | 0 | 3050
1381009 | 0 | 3700
1381214 | 0 | 3700
1381326 | 0 | 3880
1381452 | 0 | 3880
1384519 | 0 | 24250
1386005 | 0 | 3530
1386315 | 0 | 3530
1386330 | 0 | 3830
1386344 | 0 | 1480
1386743 | 0 | 2015
1387011 | 0 | 2320
1387150 | 0 | 6415
1387384 | 0 | 3060
1387685 | 0 | 1480
1387785 | 0 | 2015
1388186 | 0 | 2320
1388278 | 0 | 1880
1388446 | 0 | 3770
1388650 | 17.5259 | 880
1394289 | 0 | 2050
1397921 | 0 | 1220
1398429 | 0 | 1300
1398521 | 0 | 2990
1398866 | 0 | 2251.39
1399603 | 0 | 4715
1399781 | 0 | 3366.27
1400001 | 0 | 3442.57
1400228 | 0 | 3442.57
1400297 | 0 | 3391.5
1400561 | 0 | 4690
1400712 | 0 | 2356.77
1400928 | 0 | 11550
1401339 | 0 | 4174.24
1401642 | 0 | 6845
1402543 | 0 | 4970
1403011 | 0 | 1520
1403454 | 0 | 790
1403625 | 0 | 1550

# IfcBeam: BERSnl_28_SF_LIB_balk vierkant beton_gen_ISR:balk vierkant_gen200x350 (4)
In: 02 tweede verdieping
Type - PredefinedType: JOIST
Type - Pset_BeamCommon - IsExternal: no; LoadBearing: yes
Type - Pset_ProductRequirements - Category: Structural Framing
Type - Pset_ReinforcementBarPitchOfBeam - Description: balk 200x350
Classification: 28.10 hoofddraagconstructies; kolommen en liggers, algemeen (verzamelniveau) (Uniformat); Material: f2_beton ihwg
Pset_BeamCommon - Slope: 0 deg; IsExternal: yes; Reference: balk vierkant_gen200x350
Pset_PrecastConcreteElementGeneral - ElementWeight: 0 kg
Pset_QuantityTakeOff - Reference: balk vierkant_gen200x350
Pset_ReinforcementBarPitchOfBeam - Reference: balk vierkant_gen200x350
Name (BERSnl_28_SF_LIB_balk vierkant beton_gen_ISR:balk vierkant_gen200x350:...) | Span (mm)
838421 | 7090
838994 | 8625
839399 | 8625
839772 | 7090

# IfcBeam: BERSnl_28_SF_LIB_balk vierkant beton_gen_ISR:balk vierkant_gen500x500, BERSnl_28_SF_LIB_balk vierkant beton_gen_ISR:balk vierkant_gen500x500:561206
In: -00 fundatie
Type - PredefinedType: JOIST
Type - Pset_BeamCommon - IsExternal: no; LoadBearing: yes
Type - Pset_ProductRequirements - Category: Structural Framing
Type - Pset_ReinforcementBarPitchOfBeam - Description: balk 600x600
Classification: 28.10 hoofddraagconstructies; kolommen en liggers, algemeen (verzamelniveau) (Uniformat); Material: f2_beton ihwg
Pset_BeamCommon - Slope: 0 deg; IsExternal: yes; Reference: balk vierkant_gen500x500; Span: 5660.12 mm
Pset_PrecastConcreteElementGeneral - ElementWeight: 0 kg
Pset_QuantityTakeOff - Reference: balk vierkant_gen500x500
Pset_ReinforcementBarPitchOfBeam - Reference: balk vierkant_gen500x500

# IfcBeam: BERSnl_28_SF_LIB_balk vierkant beton_gen_ISR:balk vierkant_gen_400x600 (3)
In: -00 fundatie
Type - PredefinedType: JOIST
Type - Pset_BeamCommon - IsExternal: no; LoadBearing: yes
Type - Pset_ProductRequirements - Category: Structural Framing
Type - Pset_ReinforcementBarPitchOfBeam - Description: balk 400x600
Classification: 28.10 hoofddraagconstructies; kolommen en liggers, algemeen (verzamelniveau) (Uniformat); Material: f2_beton ihwg
Pset_BeamCommon - Slope: 0 deg; IsExternal: yes; Reference: balk vierkant_gen_400x600
Pset_PrecastConcreteElementGeneral - ElementWeight: 0 kg
Pset_QuantityTakeOff - Reference: balk vierkant_gen_400x600
Pset_ReinforcementBarPitchOfBeam - Reference: balk vierkant_gen_400x600
Name (BERSnl_28_SF_LIB_balk vierkant beton_gen_ISR:balk vierkant_gen_400x600:...) | Span (mm)
567148 | 4269.17
567317 | 3120
586950 | 3872.51

# IfcBeam: BERSnl_28_SF_LIB_balk vierkant beton_gen_ISR:balk vierkant_gen_500X600, BERSnl_28_SF_LIB_balk vierkant beton_gen_ISR:balk vierkant_gen_500X600:596466
In: -00 fundatie
Type - PredefinedType: JOIST; Classification: 28.10 hoofddraagconstructies; kolommen en liggers, algemeen (verzamelniveau) (Uniformat); Material: f2_beton ihwg
Type - Pset_BeamCommon - IsExternal: no; LoadBearing: yes
Type - Pset_ProductRequirements - Category: Structural Framing
Type - Pset_ReinforcementBarPitchOfBeam - Description: balk 600x600
Pset_BeamCommon - Slope: 0 deg; IsExternal: yes; Reference: balk vierkant_gen_500X600; Span: 3765 mm
Pset_PrecastConcreteElementGeneral - ElementWeight: 0 kg
Pset_QuantityTakeOff - Reference: balk vierkant_gen_500X600
Pset_ReinforcementBarPitchOfBeam - Reference: balk vierkant_gen_500X600

# IfcBeam: BERSnl_28_SF_LIB_balk vierkant beton_gen_ISR:balk vierkant_gen_500X600 (30)
In: -00 fundatie
Type - PredefinedType: JOIST
Type - Pset_BeamCommon - IsExternal: no; LoadBearing: yes
Type - Pset_ProductRequirements - Category: Structural Framing
Type - Pset_ReinforcementBarPitchOfBeam - Description: balk 600x600
Classification: 28.10 hoofddraagconstructies; kolommen en liggers, algemeen (verzamelniveau) (Uniformat); Material: f2_beton ihwg
Pset_BeamCommon - Slope: 0 deg; IsExternal: yes; Reference: balk vierkant_gen_500X600
Pset_PrecastConcreteElementGeneral - ElementWeight: 0 kg
Pset_QuantityTakeOff - Reference: balk vierkant_gen_500X600
Pset_ReinforcementBarPitchOfBeam - Reference: balk vierkant_gen_500X600
Name (BERSnl_28_SF_LIB_balk vierkant beton_gen_ISR:balk vierkant_gen_500X600:...) | Span (mm)
502806 | 21000
505606 | 19333.7
507241 | 12006
509378 | 24073.7
510485 | 3354
510615 | 12310
519064 | 3354
522580 | 4100.35
522625 | 14268
524177 | 4150.35
531610 | 4120
532798 | 14500
536767 | 24620
553402 | 8780
558133 | 3993.11
558402 | 3800
564596 | 1220
570616 | 11599.7
576498 | 21894
578839 | 11025
580630 | 21894
583206 | 3120
592409 | 14840
605461 | 14840
607886 | 2915
613175 | 1255
613351 | 3600.38
617752 | 4049.97
623176 | 3765
623310 | 7100

# IfcBeam: BERSnl_28_SF_LIB_balk vierkant beton_gen_ISR:balk vierkant_gen_500x850 (2)
In: -00 fundatie
Type - PredefinedType: JOIST
Type - Pset_BeamCommon - IsExternal: no; LoadBearing: yes
Type - Pset_ProductRequirements - Category: Structural Framing
Type - Pset_ReinforcementBarPitchOfBeam - Description: balk 600x850
Classification: 28.10 hoofddraagconstructies; kolommen en liggers, algemeen (verzamelniveau) (Uniformat); Material: f2_beton ihwg
Pset_BeamCommon - Slope: 0 deg; IsExternal: yes; Reference: balk vierkant_gen_500x850; Span: 600 mm
Pset_PrecastConcreteElementGeneral - ElementWeight: 0 kg
Pset_QuantityTakeOff - Reference: balk vierkant_gen_500x850
Pset_ReinforcementBarPitchOfBeam - Reference: balk vierkant_gen_500x850
Name (BERSnl_28_SF_LIB_balk vierkant beton_gen_ISR:balk vierkant_gen_500x850:...)
596742
623712

# IfcBeam: BERSnl_28_SF_LIB_balk vierkant beton_gen_ISR:balk vierkant_gen_560x600, BERSnl_28_SF_LIB_balk vierkant beton_gen_ISR:balk vierkant_gen_560x600:553643
In: -00 fundatie
Type - PredefinedType: JOIST
Type - Pset_BeamCommon - IsExternal: no; LoadBearing: yes
Type - Pset_ProductRequirements - Category: Structural Framing
Type - Pset_ReinforcementBarPitchOfBeam - Description: balk 600x600
Classification: 28.10 hoofddraagconstructies; kolommen en liggers, algemeen (verzamelniveau) (Uniformat); Material: f2_beton ihwg
Pset_BeamCommon - Slope: 0 deg; IsExternal: yes; Reference: balk vierkant_gen_560x600; Span: 11070.3 mm
Pset_PrecastConcreteElementGeneral - ElementWeight: 0 kg
Pset_QuantityTakeOff - Reference: balk vierkant_gen_560x600
Pset_ReinforcementBarPitchOfBeam - Reference: balk vierkant_gen_560x600

# IfcBeam: BERSnl_28_SF_LIB_balk vierkant beton_gen_ISR:balk vierkant_gen_600X600 (9)
In: -00 fundatie
Type - PredefinedType: JOIST
Type - Pset_BeamCommon - IsExternal: no; LoadBearing: yes
Type - Pset_ProductRequirements - Category: Structural Framing
Type - Pset_ReinforcementBarPitchOfBeam - Description: balk 600x600
Classification: 28.10 hoofddraagconstructies; kolommen en liggers, algemeen (verzamelniveau) (Uniformat); Material: f2_beton ihwg
Pset_BeamCommon - Reference: balk vierkant_gen_600X600; Slope: 0 deg; IsExternal: yes
Pset_PrecastConcreteElementGeneral - ElementWeight: 0 kg
Pset_QuantityTakeOff - Reference: balk vierkant_gen_600X600
Pset_ReinforcementBarPitchOfBeam - Reference: balk vierkant_gen_600X600
Name (BERSnl_28_SF_LIB_balk vierkant beton_gen_ISR:balk vierkant_gen_600X600:...) | Span (mm)
501836 | 24350
526078 | 24237.1
535593 | 24876.5
541235 | 9304
559199 | 3138.45
562727 | 9720
576054 | 14800
638538 | 12200
639785 | 4927.42

# IfcBeam: BERSnl_28_SF_LIB_balk vierkant beton_gen_ISR:balk vierkant_gen_600x850 (2)
In: -00 fundatie
Type - PredefinedType: JOIST
Type - Pset_BeamCommon - IsExternal: no; LoadBearing: yes
Type - Pset_ProductRequirements - Category: Structural Framing
Type - Pset_ReinforcementBarPitchOfBeam - Description: balk 600x850
Classification: 28.10 hoofddraagconstructies; kolommen en liggers, algemeen (verzamelniveau) (Uniformat); Material: f2_beton ihwg
Pset_BeamCommon - Slope: 0 deg; IsExternal: yes; Reference: balk vierkant_gen_600x850; Span: 600 mm
Pset_PrecastConcreteElementGeneral - ElementWeight: 0 kg
Pset_QuantityTakeOff - Reference: balk vierkant_gen_600x850
Pset_ReinforcementBarPitchOfBeam - Reference: balk vierkant_gen_600x850
Name (BERSnl_28_SF_LIB_balk vierkant beton_gen_ISR:balk vierkant_gen_600x850:...)
591075
1046276

# IfcBeam: BERSnl_28_SF_LIB_balk vierkant beton_gen_ISR:balk vierkant_gen_700X600, BERSnl_28_SF_LIB_balk vierkant beton_gen_ISR:balk vierkant_gen_700X600:525939
In: -00 fundatie
Type - PredefinedType: JOIST
Type - Pset_BeamCommon - IsExternal: no; LoadBearing: yes
Type - Pset_ProductRequirements - Category: Structural Framing
Type - Pset_ReinforcementBarPitchOfBeam - Description: balk 600x600
Classification: 28.10 hoofddraagconstructies; kolommen en liggers, algemeen (verzamelniveau) (Uniformat); Material: f2_beton ihwg
Pset_BeamCommon - Slope: 0 deg; IsExternal: yes; Reference: balk vierkant_gen_700X600; Span: 14400 mm
Pset_PrecastConcreteElementGeneral - ElementWeight: 0 kg
Pset_QuantityTakeOff - Reference: balk vierkant_gen_700X600
Pset_ReinforcementBarPitchOfBeam - Reference: balk vierkant_gen_700X600

# IfcBeam: BERSnl_28_SF_LIB_balk vierkant prefab_gen_ISR:balk vierkant gen 120x150, BERSnl_28_SF_LIB_balk vierkant prefab_gen_ISR:balk vierkant gen 120x150:710833
In: 01 eerste verdieping
Type - PredefinedType: JOIST
Type - Pset_BeamCommon - IsExternal: no; LoadBearing: yes
Type - Pset_ProductRequirements - Category: Structural Framing
Type - Pset_ReinforcementBarPitchOfBeam - Description: balk 400x600mm
Classification: 28.10 hoofddraagconstructies; kolommen en liggers, algemeen (verzamelniveau) (Uniformat); Material: f2_beton prefab
Pset_BeamCommon - Slope: 0 deg; IsExternal: yes; Reference: balk vierkant gen 120x150; Span: 1680 mm
Pset_PrecastConcreteElementGeneral - ElementWeight: 0 kg
Pset_QuantityTakeOff - Reference: balk vierkant gen 120x150
Pset_ReinforcementBarPitchOfBeam - Reference: balk vierkant gen 120x150

# IfcBeam: BERSnl_28_SF_LIB_balk vierkant prefab_gen_ISR:balk vierkant gen 150x210 (29)
Type - PredefinedType: JOIST
Type - Pset_BeamCommon - IsExternal: no; LoadBearing: yes
Type - Pset_ProductRequirements - Category: Structural Framing
Type - Pset_ReinforcementBarPitchOfBeam - Description: balk 400x600mm
Classification: 28.10 hoofddraagconstructies; kolommen en liggers, algemeen (verzamelniveau) (Uniformat); Material: f2_beton prefab
Pset_BeamCommon - Slope: 0 deg; IsExternal: yes; Reference: balk vierkant gen 150x210
Pset_PrecastConcreteElementGeneral - ElementWeight: 0 kg
Pset_QuantityTakeOff - Reference: balk vierkant gen 150x210
Pset_ReinforcementBarPitchOfBeam - Reference: balk vierkant gen 150x210
Name (BERSnl_28_SF_LIB_balk vierkant prefab_gen_ISR:balk vierkant gen 150x210:...) | In | Span (mm)
660674 | 01 eerste verdieping | 1500
685785 | 01 eerste verdieping | 1500
685804 | 01 eerste verdieping | 1500
713556 | 01 eerste verdieping | 840
730374 | 01 eerste verdieping | 1280
739329 | 01 eerste verdieping | 740
739947 | 01 eerste verdieping | 740
788450 | 01 eerste verdieping | 1700
807032 | 01 eerste verdieping | 1700
809740 | 01 eerste verdieping | 1700
825990 | 02 tweede verdieping | 1160
827071 | 02 tweede verdieping | 1160
833318 | 02 tweede verdieping | 1160
833343 | 02 tweede verdieping | 1160
833372 | 02 tweede verdieping | 1160
837411 | 02 tweede verdieping | 1160
837469 | 02 tweede verdieping | 1160
863344 | 02 tweede verdieping | 780
867995 | 02 tweede verdieping | 780
868018 | 02 tweede verdieping | 780
868039 | 02 tweede verdieping | 780
1215610 | 01 eerste verdieping | 1500
1393422 | 01 eerste verdieping | 2180
1456151 | 02 tweede verdieping | 1220
1456649 | 02 tweede verdieping | 1220
1456666 | 02 tweede verdieping | 1220
1456685 | 02 tweede verdieping | 1220
1456793 | 02 tweede verdieping | 1220
1456808 | 02 tweede verdieping | 1220

# IfcBeam: BERSnl_28_SF_LIB_balk vierkant prefab_gen_ISR:balk vierkant gen 214x210 (36)
Type - PredefinedType: JOIST
Type - Pset_BeamCommon - IsExternal: no; LoadBearing: yes
Type - Pset_ProductRequirements - Category: Structural Framing
Type - Pset_ReinforcementBarPitchOfBeam - Description: balk 400x600mm
Classification: 28.10 hoofddraagconstructies; kolommen en liggers, algemeen (verzamelniveau) (Uniformat); Material: f2_beton prefab
Pset_BeamCommon - Slope: 0 deg; IsExternal: yes; Reference: balk vierkant gen 214x210
Pset_PrecastConcreteElementGeneral - ElementWeight: 0 kg
Pset_QuantityTakeOff - Reference: balk vierkant gen 214x210
Pset_ReinforcementBarPitchOfBeam - Reference: balk vierkant gen 214x210
Name (BERSnl_28_SF_LIB_balk vierkant prefab_gen_ISR:balk vierkant gen 214x210:...) | In | Span (mm)
670294 | 01 eerste verdieping | 2200
671898 | 01 eerste verdieping | 2200
672487 | 01 eerste verdieping | 2200
672942 | 01 eerste verdieping | 2366.39
719054 | 01 eerste verdieping | 1540
721604 | 01 eerste verdieping | 1540
722288 | 01 eerste verdieping | 1540
727997 | 01 eerste verdieping | 1540
754813 | 01 eerste verdieping | 1080
755166 | 01 eerste verdieping | 1080
773190 | 01 eerste verdieping | 2300
773972 | 01 eerste verdieping | 2300
773999 | 01 eerste verdieping | 2300
774480 | 01 eerste verdieping | 2300
811568 | 01 eerste verdieping | 1200
813129 | 01 eerste verdieping | 1200
813152 | 01 eerste verdieping | 1200
813415 | 01 eerste verdieping | 1200
829453 | 02 tweede verdieping | 1580
830292 | 02 tweede verdieping | 1580
830371 | 02 tweede verdieping | 1650
830392 | 02 tweede verdieping | 1650
830711 | 02 tweede verdieping | 1580
830757 | 02 tweede verdieping | 1644.63
830779 | 02 tweede verdieping | 1644.63
871018 | 02 tweede verdieping | 780
871132 | 02 tweede verdieping | 780
871149 | 02 tweede verdieping | 780
871174 | 02 tweede verdieping | 780
882938 | 02 tweede verdieping | 1860
883045 | 02 tweede verdieping | 510.731
887714 | 02 tweede verdieping | 520
896981 | 02 tweede verdieping | 660
919404 | 02 tweede verdieping | 2200
1226237 | 01 eerste verdieping | 2200
1240567 | 02 tweede verdieping | 1080

# IfcBeam: BERSnl_28_SF_LIB_balk vierkant prefab_gen_ISR:balk vierkant gen 214x300 (2)
Type - PredefinedType: JOIST
Type - Pset_BeamCommon - IsExternal: no; LoadBearing: yes
Type - Pset_ProductRequirements - Category: Structural Framing
Type - Pset_ReinforcementBarPitchOfBeam - Description: balk 400x600mm
Classification: 28.10 hoofddraagconstructies; kolommen en liggers, algemeen (verzamelniveau) (Uniformat); Material: f2_beton prefab
Pset_BeamCommon - Slope: 0 deg; IsExternal: yes; Reference: balk vierkant gen 214x300
Pset_PrecastConcreteElementGeneral - ElementWeight: 0 kg
Pset_QuantityTakeOff - Reference: balk vierkant gen 214x300
Pset_ReinforcementBarPitchOfBeam - Reference: balk vierkant gen 214x300
Name (BERSnl_28_SF_LIB_balk vierkant prefab_gen_ISR:balk vierkant gen 214x300:...) | In | Span (mm)
1232956 | 02 tweede verdieping | 2800
1249232 | 01 eerste verdieping | 2500

# IfcColumn: BERSnl_28_SCO_TLB_kolom hea_gen_ISR:kolom gen hea140 (10)
In: 02 tweede verdieping
Type - PredefinedType: COLUMN; Classification: 28.10 hoofddraagconstructies; kolommen en liggers, algemeen (verzamelniveau) (Uniformat); Material: h2_staal
Type - Pset_ColumnCommon - IsExternal: no; LoadBearing: yes
Type - Pset_ProductRequirements - Category: Structural Columns
Type - Pset_ReinforcementBarPitchOfColumn - Description: HEA140
Pset_ColumnCommon - IsExternal: yes; Reference: kolom gen hea140
Pset_PrecastConcreteElementGeneral - ElementWeight: 0 kg
Pset_QuantityTakeOff - Reference: kolom gen hea140
Pset_ReinforcementBarPitchOfColumn - Reference: kolom gen hea140
Name (BERSnl_28_SCO_TLB_kolom hea_gen_ISR:kolom gen hea140:...)
841089
841356
841386
842418
842441
842458
842477
842500
842517
842696

# IfcColumn: BERSnl_28_SCO_TLB_kolom hea_gen_ISR:kolom gen hea180, BERSnl_28_SCO_TLB_kolom hea_gen_ISR:kolom gen hea180:1291620
In: -00 fundatie
Type - PredefinedType: COLUMN; Classification: 28.10 hoofddraagconstructies; kolommen en liggers, algemeen (verzamelniveau) (Uniformat); Material: <Unnamed>, 00_Staal_generiek
Type - Pset_ColumnCommon - IsExternal: no; LoadBearing: yes; FireRating: 90
Type - Pset_ConcreteElementGeneral - FireRating: 90
Type - Pset_ProductRequirements - Category: Structural Columns
Type - Pset_ReinforcementBarPitchOfColumn - Description: HEA180
Pset_ColumnCommon - IsExternal: yes; Reference: kolom gen hea180
Pset_PrecastConcreteElementGeneral - ElementWeight: 0 kg
Pset_QuantityTakeOff - Reference: kolom gen hea180
Pset_ReinforcementBarPitchOfColumn - Reference: kolom gen hea180

# IfcColumn: BERSnl_28_SCO_TLB_kolom hea_gen_ISR:kolom gen hea180 (14)
In: -00 fundatie
Type - PredefinedType: COLUMN; Classification: 28.10 hoofddraagconstructies; kolommen en liggers, algemeen (verzamelniveau) (Uniformat); Material: h2_staal
Type - Pset_ColumnCommon - IsExternal: no; LoadBearing: yes; FireRating: 90
Type - Pset_ConcreteElementGeneral - FireRating: 90
Type - Pset_ProductRequirements - Category: Structural Columns
Type - Pset_ReinforcementBarPitchOfColumn - Description: HEA180
Pset_ColumnCommon - IsExternal: yes; Reference: kolom gen hea180
Pset_PrecastConcreteElementGeneral - ElementWeight: 0 kg
Pset_QuantityTakeOff - Reference: kolom gen hea180
Pset_ReinforcementBarPitchOfColumn - Reference: kolom gen hea180
Name (BERSnl_28_SCO_TLB_kolom hea_gen_ISR:kolom gen hea180:...)
527929
529967
529984
530011
530036
534776
534997
535869
537625
537718
537748
539409
540580
547350

# IfcColumn: BERSnl_28_SCO_TLB_kolom hea_gen_ISR:kolom gen hea220 (27)
Type - PredefinedType: COLUMN; Classification: 28.10 hoofddraagconstructies; kolommen en liggers, algemeen (verzamelniveau) (Uniformat); Material: <Unnamed>, 00_Staal_generiek
Type - Pset_ColumnCommon - IsExternal: no; LoadBearing: yes; FireRating: 90
Type - Pset_ConcreteElementGeneral - FireRating: 90
Type - Pset_ProductRequirements - Category: Structural Columns
Type - Pset_ReinforcementBarPitchOfColumn - Description: HEA220
Pset_ColumnCommon - IsExternal: yes; Reference: kolom gen hea220
Pset_PrecastConcreteElementGeneral - ElementWeight: 0 kg
Pset_QuantityTakeOff - Reference: kolom gen hea220
Pset_ReinforcementBarPitchOfColumn - Reference: kolom gen hea220
Name (BERSnl_28_SCO_TLB_kolom hea_gen_ISR:kolom gen hea220:...) | In
581308 | -00 fundatie
592593 | 00 begane grond
594784 | 00 begane grond
595742 | 00 begane grond
595778 | 00 begane grond | Pset_ColumnCommon - Slope: 0 deg
595810 | -00 fundatie
605227 | 00 begane grond
606397 | 00 begane grond
606887 | 00 begane grond
606922 | 00 begane grond | Pset_ColumnCommon - Slope: 0 deg
608201 | -00 fundatie
608643 | -00 fundatie
624450 | 00 begane grond
647822 | -00 fundatie
681514 | 01 eerste verdieping
779424 | 01 eerste verdieping
781925 | 01 eerste verdieping
782235 | 01 eerste verdieping
783860 | 01 eerste verdieping
784333 | 01 eerste verdieping
791720 | 01 eerste verdieping
792087 | 01 eerste verdieping | Pset_ColumnCommon - Slope: 0 deg
802671 | 01 eerste verdieping
804319 | -00 fundatie
815764 | 01 eerste verdieping
900575 | 01 eerste verdieping
904199 | 01 eerste verdieping

# IfcColumn: BERSnl_28_SCO_TLB_kolom hea_gen_ISR:kolom gen hea220 (36)
Type - PredefinedType: COLUMN; Classification: 28.10 hoofddraagconstructies; kolommen en liggers, algemeen (verzamelniveau) (Uniformat); Material: h2_staal
Type - Pset_ColumnCommon - IsExternal: no; LoadBearing: yes; FireRating: 90
Type - Pset_ConcreteElementGeneral - FireRating: 90
Type - Pset_ProductRequirements - Category: Structural Columns
Type - Pset_ReinforcementBarPitchOfColumn - Description: HEA220
Pset_ColumnCommon - IsExternal: yes; Reference: kolom gen hea220
Pset_PrecastConcreteElementGeneral - ElementWeight: 0 kg
Pset_QuantityTakeOff - Reference: kolom gen hea220
Pset_ReinforcementBarPitchOfColumn - Reference: kolom gen hea220
Name (BERSnl_28_SCO_TLB_kolom hea_gen_ISR:kolom gen hea220:...) | In
503257 | -00 fundatie
506332 | -00 fundatie
507048 | -00 fundatie
507075 | -00 fundatie
507102 | -00 fundatie
507777 | -00 fundatie
507964 | -00 fundatie
509190 | -00 fundatie
510062 | -00 fundatie
510097 | -00 fundatie
510126 | -00 fundatie
510155 | -00 fundatie
510190 | -00 fundatie
510952 | -00 fundatie
511403 | -00 fundatie
515469 | -00 fundatie
515776 | -00 fundatie
515809 | -00 fundatie
556665 | -00 fundatie
564541 | -00 fundatie
565687 | -00 fundatie
657809 | 01 eerste verdieping
662718 | 01 eerste verdieping
663426 | 01 eerste verdieping
663710 | 01 eerste verdieping
664018 | 01 eerste verdieping
665303 | 01 eerste verdieping
667040 | -00 fundatie
677241 | 01 eerste verdieping
682918 | 01 eerste verdieping
702452 | 01 eerste verdieping
706786 | 01 eerste verdieping
723537 | 01 eerste verdieping
724804 | 01 eerste verdieping
725793 | 01 eerste verdieping
835264 | 01 eerste verdieping

# IfcColumn: BERSnl_28_SCO_TLB_kolom heb_gen_ISR:kolom gen heb220, BERSnl_28_SCO_TLB_kolom heb_gen_ISR:kolom gen heb220:556681
In: -00 fundatie
Type - PredefinedType: COLUMN; Classification: 28.10 hoofddraagconstructies; kolommen en liggers, algemeen (verzamelniveau) (Uniformat); Material: h2_staal
Type - Pset_ColumnCommon - IsExternal: no; LoadBearing: yes
Type - Pset_ProductRequirements - Category: Structural Columns
Type - Pset_ReinforcementBarPitchOfColumn - Description: HEB220
Pset_ColumnCommon - Slope: 0 deg; IsExternal: yes; Reference: kolom gen heb220
Pset_PrecastConcreteElementGeneral - ElementWeight: 0 kg
Pset_QuantityTakeOff - Reference: kolom gen heb220
Pset_ReinforcementBarPitchOfColumn - Reference: kolom gen heb220

# IfcColumn: BERSnl_28_SCO_TLB_kolom koker_gen_ISR:kolom gen K150x150x8, BERSnl_28_SCO_TLB_kolom koker_gen_ISR:kolom gen K150x150x8:1292453
In: 01 eerste verdieping
Type - PredefinedType: COLUMN; Classification: 28.10 hoofddraagconstructies; kolommen en liggers, algemeen (verzamelniveau) (Uniformat); Material: 00_Staal_generiek
Type - Pset_ColumnCommon - IsExternal: no; LoadBearing: yes
Type - Pset_ProductRequirements - Category: Structural Columns
Type - Pset_ReinforcementBarPitchOfColumn - Description: K80x80x8
Pset_ColumnCommon - IsExternal: yes; Reference: kolom gen K150x150x8
Pset_PrecastConcreteElementGeneral - ElementWeight: 0 kg
Pset_QuantityTakeOff - Reference: kolom gen K150x150x8
Pset_ReinforcementBarPitchOfColumn - Reference: kolom gen K150x150x8

# IfcColumn: BERSnl_28_SCO_TLB_kolom koker_gen_ISR:kolom gen k80x80x8 (2)
In: -00 fundatie
Type - PredefinedType: COLUMN; Classification: 28.10 hoofddraagconstructies; kolommen en liggers, algemeen (verzamelniveau) (Uniformat); Material: 00_Staal_generiek
Type - Pset_ColumnCommon - IsExternal: no; LoadBearing: yes; FireRating: 90
Type - Pset_ConcreteElementGeneral - FireRating: 90
Type - Pset_ProductRequirements - Category: Structural Columns
Type - Pset_ReinforcementBarPitchOfColumn - Description: K80x80x8
Pset_ColumnCommon - IsExternal: yes; Reference: kolom gen k80x80x8
Pset_PrecastConcreteElementGeneral - ElementWeight: 0 kg
Pset_QuantityTakeOff - Reference: kolom gen k80x80x8
Pset_ReinforcementBarPitchOfColumn - Reference: kolom gen k80x80x8
Name (BERSnl_28_SCO_TLB_kolom koker_gen_ISR:kolom gen k80x80x8:...)
513950
514954

# IfcColumn: BERSnl_28_SCO_TLB_kolom unp_gen_ISR:kolom_gen_UNP140 (10)
Type - PredefinedType: COLUMN; Classification: 28.10 hoofddraagconstructies; kolommen en liggers, algemeen (verzamelniveau) (Uniformat); Material: <Unnamed>, 00_Staal_generiek
Type - Pset_ColumnCommon - IsExternal: no; LoadBearing: yes
Type - Pset_ProductRequirements - Category: Structural Columns
Type - Pset_ReinforcementBarPitchOfColumn - Description: UNP140
Pset_ColumnCommon - IsExternal: yes; Reference: kolom_gen_UNP140
Pset_PrecastConcreteElementGeneral - ElementWeight: 0 kg
Pset_QuantityTakeOff - Reference: kolom_gen_UNP140
Pset_ReinforcementBarPitchOfColumn - Reference: kolom_gen_UNP140
Name (BERSnl_28_SCO_TLB_kolom unp_gen_ISR:kolom_gen_UNP140:...) | In
942438 | -00 fundatie
942851 | -00 fundatie
942962 | -00 fundatie
957706 | -00 fundatie
1059562 | -00 fundatie
1060202 | -00 fundatie
1066302 | -00 fundatie
1067664 | -00 fundatie
1207005 | -00 fundatie
1381747 | 02 tweede verdieping

# IfcColumn: BERSnl_28_SCO_TLB_kolom unp_gen_ISR:kolom_gen_UNP140 (2)
In: -00 fundatie
Type - PredefinedType: COLUMN; Classification: 28.10 hoofddraagconstructies; kolommen en liggers, algemeen (verzamelniveau) (Uniformat); Material: h2_staal
Type - Pset_ColumnCommon - IsExternal: no; LoadBearing: yes
Type - Pset_ProductRequirements - Category: Structural Columns
Type - Pset_ReinforcementBarPitchOfColumn - Description: UNP140
Pset_ColumnCommon - Slope: 0 deg; IsExternal: yes; Reference: kolom_gen_UNP140
Pset_PrecastConcreteElementGeneral - ElementWeight: 0 kg
Pset_QuantityTakeOff - Reference: kolom_gen_UNP140
Pset_ReinforcementBarPitchOfColumn - Reference: kolom_gen_UNP140
Name (BERSnl_28_SCO_TLB_kolom unp_gen_ISR:kolom_gen_UNP140:...)
937934
938319

# IfcColumn: BERSnl_28_SCO_TLB_kolom vierkant beton_gen_ISR:200x150 (10)
In: -00 fundatie
Type - PredefinedType: COLUMN; Classification: 28.10 hoofddraagconstructies; kolommen en liggers, algemeen (verzamelniveau) (Uniformat); Material: f2_beton
Type - Pset_ColumnCommon - IsExternal: no; LoadBearing: yes
Type - Pset_ProductRequirements - Category: Structural Columns
Type - Pset_ReinforcementBarPitchOfColumn - Description: Betonkolom 300x300mm
Pset_ColumnCommon - IsExternal: yes; Reference: 200x150
Pset_PrecastConcreteElementGeneral - ElementWeight: 0 kg
Pset_QuantityTakeOff - Reference: 200x150
Pset_ReinforcementBarPitchOfColumn - Reference: 200x150
Name (BERSnl_28_SCO_TLB_kolom vierkant beton_gen_ISR:200x150:...)
1054701
1056586
1060261 | Pset_ColumnCommon - Slope: 0 deg
1060483 | Pset_ColumnCommon - Slope: 0 deg
1066377 | Pset_ColumnCommon - Slope: 0 deg
1067824 | Pset_ColumnCommon - Slope: 0 deg
1070550
1070663
1070996
1208810 | Pset_ColumnCommon - Slope: 0 deg

# IfcColumn: BERSnl_28_SCO_TLB_kolom vierkant beton_gen_ISR:300x200 (2)
In: -00 fundatie
Type - PredefinedType: COLUMN; Classification: 28.10 hoofddraagconstructies; kolommen en liggers, algemeen (verzamelniveau) (Uniformat); Material: <Unnamed>
Type - Pset_ColumnCommon - IsExternal: no; LoadBearing: yes
Type - Pset_ProductRequirements - Category: Structural Columns
Type - Pset_ReinforcementBarPitchOfColumn - Description: Betonkolom 300x300mm
Pset_ColumnCommon - IsExternal: yes; Reference: 300x200
Pset_PrecastConcreteElementGeneral - ElementWeight: 0 kg
Pset_QuantityTakeOff - Reference: 300x200
Pset_ReinforcementBarPitchOfColumn - Reference: 300x200
Name (BERSnl_28_SCO_TLB_kolom vierkant beton_gen_ISR:300x200:...)
519519 | Pset_ColumnCommon - Slope: 0 deg
520339

# IfcColumn: BERSnl_28_SCO_TLB_kolom vierkant beton_gen_ISR:300x200, BERSnl_28_SCO_TLB_kolom vierkant beton_gen_ISR:300x200:535235
In: -00 fundatie
Type - PredefinedType: COLUMN; Classification: 28.10 hoofddraagconstructies; kolommen en liggers, algemeen (verzamelniveau) (Uniformat); Material: f2_beton
Type - Pset_ColumnCommon - IsExternal: no; LoadBearing: yes
Type - Pset_ProductRequirements - Category: Structural Columns
Type - Pset_ReinforcementBarPitchOfColumn - Description: Betonkolom 300x300mm
Pset_ColumnCommon - Slope: 0 deg; IsExternal: yes; Reference: 300x200
Pset_PrecastConcreteElementGeneral - ElementWeight: 0 kg
Pset_QuantityTakeOff - Reference: 300x200
Pset_ReinforcementBarPitchOfColumn - Reference: 300x200

# IfcColumn: BERSnl_28_SCO_TLB_kolom vierkant beton_gen_ISR:300x230 (2)
In: -00 fundatie
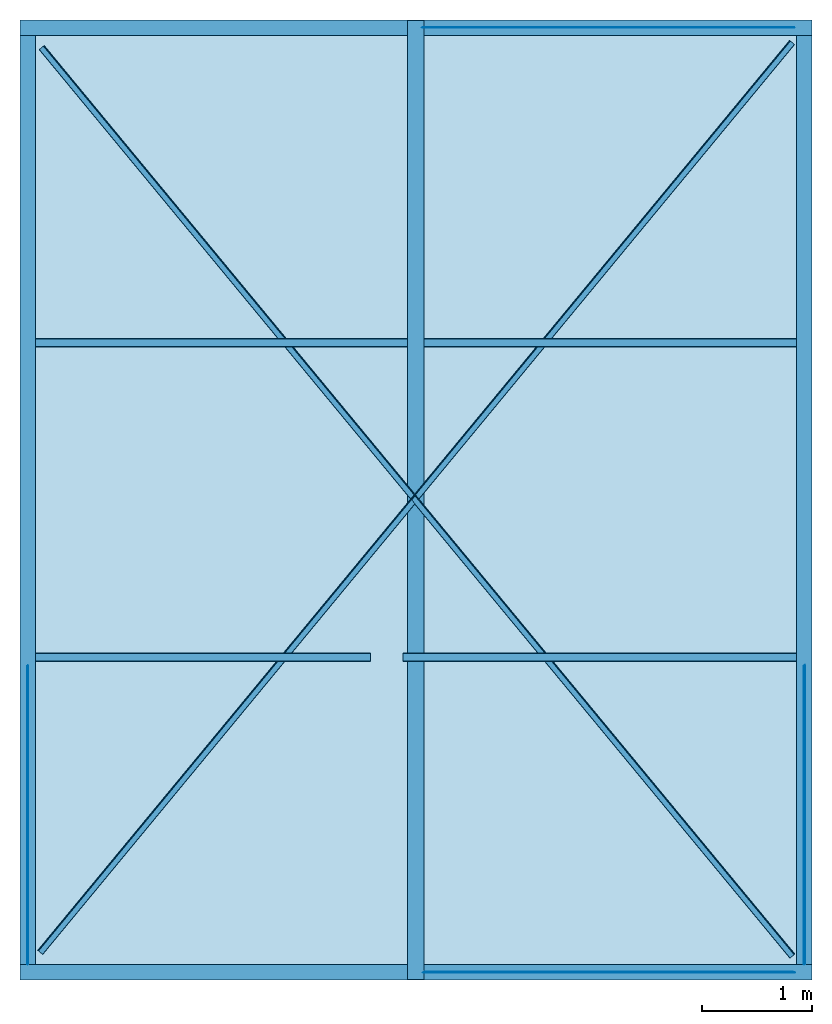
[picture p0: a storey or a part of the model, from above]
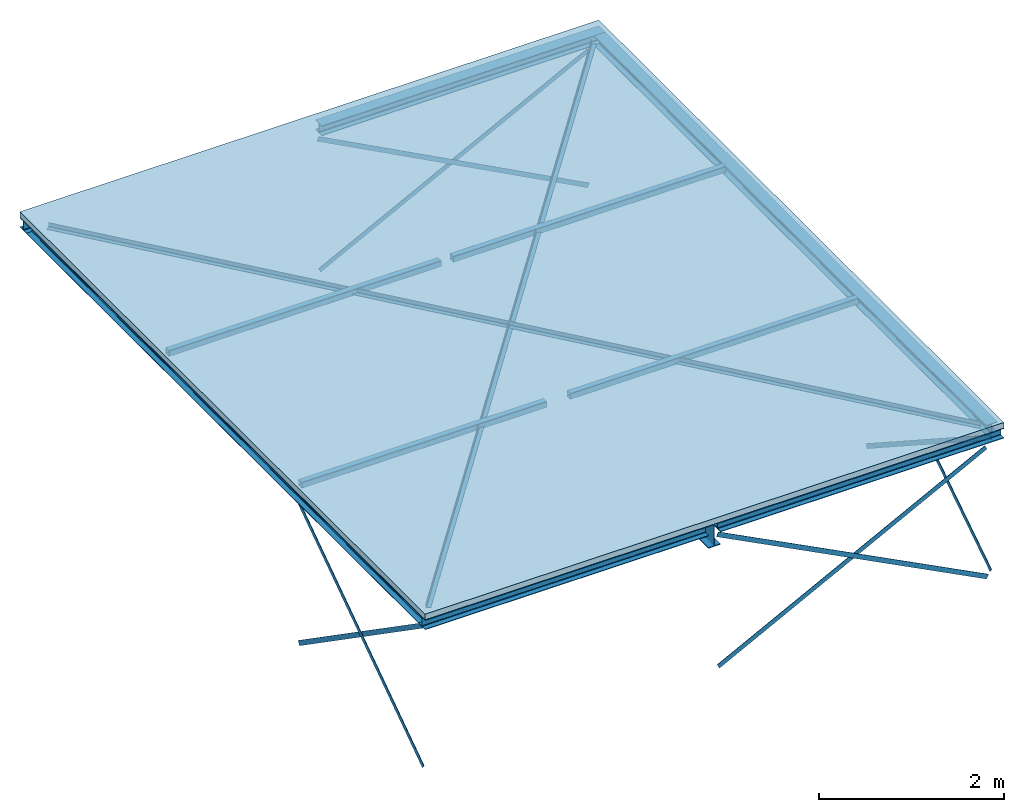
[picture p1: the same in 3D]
Properties of the parts of a building model (IFC2X3), part 2 of 2

# IfcColumn: BERSnl_28_SCO_TLB_kolom vierkant beton_gen_ISR:300x230 (2)
Type - PredefinedType: COLUMN; Classification: 28.10 hoofddraagconstructies; kolommen en liggers, algemeen (verzamelniveau) (Uniformat); Material: f2_beton
Type - Pset_ColumnCommon - IsExternal: no; LoadBearing: yes
Type - Pset_ProductRequirements - Category: Structural Columns
Type - Pset_ReinforcementBarPitchOfColumn - Description: Betonkolom 300x300mm
Pset_ColumnCommon - IsExternal: yes; Reference: 300x230
Pset_PrecastConcreteElementGeneral - ElementWeight: 0 kg
Pset_QuantityTakeOff - Reference: 300x230
Pset_ReinforcementBarPitchOfColumn - Reference: 300x230
Name (BERSnl_28_SCO_TLB_kolom vierkant beton_gen_ISR:300x230:...)
539411
540530

# IfcColumn: BERSnl_28_SCO_TLB_kolom vierkant beton_gen_ISR:300x300 (15)
Type - PredefinedType: COLUMN; Classification: 28.10 hoofddraagconstructies; kolommen en liggers, algemeen (verzamelniveau) (Uniformat); Material: <Unnamed>
Type - Pset_ColumnCommon - IsExternal: no; LoadBearing: yes
Type - Pset_ProductRequirements - Category: Structural Columns
Type - Pset_ReinforcementBarPitchOfColumn - Description: Betonkolom 300x300mm
Pset_ColumnCommon - IsExternal: yes; Reference: 300x300
Pset_PrecastConcreteElementGeneral - ElementWeight: 0 kg
Pset_QuantityTakeOff - Reference: 300x300
Pset_ReinforcementBarPitchOfColumn - Reference: 300x300
Name (BERSnl_28_SCO_TLB_kolom vierkant beton_gen_ISR:300x300:...) | In
581826 | -00 fundatie
593397 | 00 begane grond
595591 | 00 begane grond
595744 | 00 begane grond
595780 | 00 begane grond | Pset_ColumnCommon - Slope: 0 deg
595812 | -00 fundatie
605230 | 00 begane grond
606399 | 00 begane grond
606889 | 00 begane grond
606924 | 00 begane grond | Pset_ColumnCommon - Slope: 0 deg
608203 | -00 fundatie
608645 | -00 fundatie
624452 | 00 begane grond | Pset_ColumnCommon - Slope: 0 deg
633716 | -00 fundatie | Pset_ColumnCommon - Slope: 0 deg
647824 | -00 fundatie

# IfcColumn: BERSnl_28_SCO_TLB_kolom vierkant beton_gen_ISR:300x300 (32)
In: -00 fundatie
Type - PredefinedType: COLUMN; Classification: 28.10 hoofddraagconstructies; kolommen en liggers, algemeen (verzamelniveau) (Uniformat); Material: f2_beton
Type - Pset_ColumnCommon - IsExternal: no; LoadBearing: yes
Type - Pset_ProductRequirements - Category: Structural Columns
Type - Pset_ReinforcementBarPitchOfColumn - Description: Betonkolom 300x300mm
Pset_ColumnCommon - IsExternal: yes; Reference: 300x300
Pset_PrecastConcreteElementGeneral - ElementWeight: 0 kg
Pset_QuantityTakeOff - Reference: 300x300
Pset_ReinforcementBarPitchOfColumn - Reference: 300x300
Name (BERSnl_28_SCO_TLB_kolom vierkant beton_gen_ISR:300x300:...)
504006
506518
507050
507077
507104
507779
507966
509192
510064
510099
510128
510157
510192
510954 | Pset_ColumnCommon - Slope: 0 deg
511405
515471
515778
515811
530246 | Pset_ColumnCommon - Slope: 0 deg
530507
530523 | Pset_ColumnCommon - Slope: 0 deg
530547 | Pset_ColumnCommon - Slope: 0 deg
533258 | Pset_ColumnCommon - Slope: 0 deg
535437 | Pset_ColumnCommon - Slope: 0 deg
535994 | Pset_ColumnCommon - Slope: 0 deg
537627
537720 | Pset_ColumnCommon - Slope: 0 deg
537750 | Pset_ColumnCommon - Slope: 0 deg
547353 | Pset_ColumnCommon - Slope: 0 deg
556741 | Pset_ColumnCommon - Slope: 0 deg
580566
1389820

# IfcOpeningElement: Opening (121)
Pset_ElementShading - Roughness: 304.8 mm
Pset_OpeningElementCommon - sets with these values: 2
Name | In | Classification | Reference | Category
5 x Basic Wall:BERSnl_22_WA_kalkzandsteen214:500331 | -00 fundatie | 22.21 binnenwanden; constructief, massieve wanden (Uniformat) | BERSnl_22_WA_kalkzandsteen214 | Walls: Rectangular Straight Wall Opening
2 x Basic Wall:BERSnl_22_WA_kalkzandsteen150:500333 | -00 fundatie | 22.21 binnenwanden; constructief, massieve wanden (Uniformat) | BERSnl_22_WA_kalkzandsteen150 | Walls: Rectangular Straight Wall Opening
11 x Basic Wall:BERSnl_22_WA_kalkzandsteen150:500338 | -00 fundatie | 22.21 binnenwanden; constructief, massieve wanden (Uniformat) | BERSnl_22_WA_kalkzandsteen150 | Lines: <Sketch>
2 x Basic Wall:BERSnl_22_WA_kalkzandsteen150:508973 | -00 fundatie | 22.21 binnenwanden; constructief, massieve wanden (Uniformat) | BERSnl_22_WA_kalkzandsteen150 | Walls: Rectangular Straight Wall Opening
Basic Wall:BERSnl_22_WA_kalkzandsteen 120_gen_ISR:521499 | -00 fundatie | 22.21 binnenwanden; constructief, massieve wanden (Uniformat) | BERSnl_22_WA_kalkzandsteen 120_gen_ISR | Walls: Rectangular Straight Wall Opening
Basic Wall:BERSnl_22_WA_kalkzandsteen150:524999 | -00 fundatie | 22.21 binnenwanden; constructief, massieve wanden (Uniformat) | BERSnl_22_WA_kalkzandsteen150 | Walls: Rectangular Straight Wall Opening
3 x Basic Wall:BERSnl_22_WA_kalkzandsteen 100_gen_ISR:525452 | -00 fundatie | 22.21 binnenwanden; constructief, massieve wanden (Uniformat) | BERSnl_22_WA_kalkzandsteen 100_gen_ISR | Lines: <Sketch>
Basic Wall:BERSnl_22_WA_kalkzandsteen 100_gen_ISR:540920 | -00 fundatie | 22.21 binnenwanden; constructief, massieve wanden (Uniformat) | BERSnl_22_WA_kalkzandsteen 100_gen_ISR | Walls: Rectangular Straight Wall Opening
 | -00 fundatie | 23.20 vloeren; constructief, algemeen (verzamelniveau) (Uniformat) | BERSnl_23_FL_kanaalplaatvloer 265 | Floors
Basic Wall:BERSnl_22_WA_kalkzandsteen150:557927 | -00 fundatie | 22.21 binnenwanden; constructief, massieve wanden (Uniformat) | BERSnl_22_WA_kalkzandsteen150 | Walls: Rectangular Straight Wall Opening
4 x Basic Wall:BERSnl_22_WA_kalkzandsteen214:571963 | 00 begane grond | 22.21 binnenwanden; constructief, massieve wanden (Uniformat) | BERSnl_22_WA_kalkzandsteen214 | Walls: Rectangular Straight Wall Opening
2 x Basic Wall:BERSnl_22_WA_kalkzandsteen150:576330 | 00 begane grond | 22.21 binnenwanden; constructief, massieve wanden (Uniformat) | BERSnl_22_WA_kalkzandsteen150 | Walls: Rectangular Straight Wall Opening
4 x Basic Wall:BERSnl_22_WA_kalkzandsteen150:500338 | 00 begane grond | 22.21 binnenwanden; constructief, massieve wanden (Uniformat) | BERSnl_22_WA_kalkzandsteen150 | Lines: <Sketch>
2 x Basic Wall:BERSnl_22_WA_kalkzandsteen150:593741 | 00 begane grond | 22.21 binnenwanden; constructief, massieve wanden (Uniformat) | BERSnl_22_WA_kalkzandsteen150 | Walls: Rectangular Straight Wall Opening
2 x Basic Wall:BERSnl_22_WA_kalkzandsteen150:638856 | 00 begane grond | 22.21 binnenwanden; constructief, massieve wanden (Uniformat) | BERSnl_22_WA_kalkzandsteen150 | Walls: Rectangular Straight Wall Opening
4 x Basic Wall:BERSnl_22_WA_kalkzandsteen214:638965 | 00 begane grond | 22.21 binnenwanden; constructief, massieve wanden (Uniformat) | BERSnl_22_WA_kalkzandsteen214 | Walls: Rectangular Straight Wall Opening
Basic Wall:BERSnl_22_WA_kalkzandsteen214:500336 | 00 begane grond | 22.21 binnenwanden; constructief, massieve wanden (Uniformat) | BERSnl_22_WA_kalkzandsteen214 | Lines: <Sketch>
 | -00 fundatie | 23.10 vloeren; niet constructief, algemeen (verzamelniveau) (Uniformat) | NLRS_23_FL_isolatie 130 | Floors
9 x  | 01 eerste verdieping | 23.20 vloeren; constructief, algemeen (verzamelniveau) (Uniformat) | BERSnl_23_FL_druklaag 60 | Floors
2 x Basic Wall:BERSnl_22_WA_kalkzandsteen150:668638 | 01 eerste verdieping | 22.21 binnenwanden; constructief, massieve wanden (Uniformat) | BERSnl_22_WA_kalkzandsteen150 | Walls: Rectangular Straight Wall Opening
7 x Basic Wall:BERSnl_22_WA_kalkzandsteen214:676283 | 01 eerste verdieping | 22.21 binnenwanden; constructief, massieve wanden (Uniformat) | BERSnl_22_WA_kalkzandsteen214 | Walls: Rectangular Straight Wall Opening
3 x Basic Wall:BERSnl_22_WA_kalkzandsteen150:686158 | 01 eerste verdieping | 22.21 binnenwanden; constructief, massieve wanden (Uniformat) | BERSnl_22_WA_kalkzandsteen150 | Walls: Rectangular Straight Wall Opening
 | 01 eerste verdieping | 23.20 vloeren; constructief, algemeen (verzamelniveau) (Uniformat) | BERSnl_23_FL_kanaalplaatvloer 260_gen_ISR | Floors
7 x  | 01 eerste verdieping | 23.20 vloeren; constructief, algemeen (verzamelniveau) (Uniformat) | BERSnl_23_FL_kanaalplaatvloer 200_gen_ISR | Floors
2 x Basic Wall:BERSnl_22_WA_kalkzandsteen150:711769 | 01 eerste verdieping | 22.21 binnenwanden; constructief, massieve wanden (Uniformat) | BERSnl_22_WA_kalkzandsteen150 | Walls: Rectangular Straight Wall Opening
4 x Basic Wall:BERSnl_22_WA_kalkzandsteen150:712043 | 01 eerste verdieping | 22.21 binnenwanden; constructief, massieve wanden (Uniformat) | BERSnl_22_WA_kalkzandsteen150 | Walls: Rectangular Straight Wall Opening
2 x Basic Wall:BERSnl_22_WA_kalkzandsteen150:736952 | -00 fundatie | 22.21 binnenwanden; constructief, massieve wanden (Uniformat) | BERSnl_22_WA_kalkzandsteen150 | Walls: Rectangular Straight Wall Opening
6 x Basic Wall:BERSnl_22_WA_kalkzandsteen214:817353 | 01 eerste verdieping | 22.21 binnenwanden; constructief, massieve wanden (Uniformat) | BERSnl_22_WA_kalkzandsteen214 | Walls: Rectangular Straight Wall Opening
3 x Basic Wall:BERSnl_22_WA_kalkzandsteen214:818536 | 01 eerste verdieping | 22.21 binnenwanden; constructief, massieve wanden (Uniformat) | BERSnl_22_WA_kalkzandsteen214 | Walls: Rectangular Straight Wall Opening
Basic Wall:BERSnl_22_WA_kalkzandsteen214:819006 | 01 eerste verdieping | 22.21 binnenwanden; constructief, massieve wanden (Uniformat) | BERSnl_22_WA_kalkzandsteen214 | Walls: Rectangular Straight Wall Opening
5 x  | 02 tweede verdieping | 23.20 vloeren; constructief, algemeen (verzamelniveau) (Uniformat) | BERSnl_23_FL_druklaag 60 | Floors
5 x  | 02 tweede verdieping | 23.20 vloeren; constructief, algemeen (verzamelniveau) (Uniformat) | BERSnl_23_FL_kanaalplaatvloer 200_gen_ISR | Floors
Basic Wall:BERSnl_22_WA_kalkzandsteen214:912669 | 01 eerste verdieping | 22.21 binnenwanden; constructief, massieve wanden (Uniformat) | BERSnl_22_WA_kalkzandsteen214 | Walls: Rectangular Straight Wall Opening
2 x Basic Wall:BERSnl_22_WA_kalkzandsteen 100_gen_ISR:1154397 | -00 fundatie | 22.21 binnenwanden; constructief, massieve wanden (Uniformat) | BERSnl_22_WA_kalkzandsteen 100_gen_ISR | Walls: Rectangular Straight Wall Opening
Basic Wall:BERSnl_22_WA_kalkzandsteen 100_gen_ISR:1207897 | -00 fundatie | 22.21 binnenwanden; constructief, massieve wanden (Uniformat) | BERSnl_22_WA_kalkzandsteen 100_gen_ISR | Walls: Rectangular Straight Wall Opening
Basic Wall:BERSnl_22_WA_kalkzandsteen 100_gen_ISR:1209942 | -00 fundatie | 22.21 binnenwanden; constructief, massieve wanden (Uniformat) | BERSnl_22_WA_kalkzandsteen 100_gen_ISR | Walls: Rectangular Straight Wall Opening
Basic Wall:BERSnl_22_WA_kalkzandsteen214:1246842 | -00 fundatie | 22.21 binnenwanden; constructief, massieve wanden (Uniformat) | BERSnl_22_WA_kalkzandsteen214 | Walls: Rectangular Straight Wall Opening
Basic Wall:BERSnl_22_WA_kalkzandsteen150:1388924 | -00 fundatie | 22.21 binnenwanden; constructief, massieve wanden (Uniformat) | BERSnl_22_WA_kalkzandsteen150 | Walls: Rectangular Straight Wall Opening
2 x Basic Wall:BERSnl_22_WA_kalkzandsteen150:1452254 | 01 eerste verdieping | 22.21 binnenwanden; constructief, massieve wanden (Uniformat) | BERSnl_22_WA_kalkzandsteen150 | Walls: Rectangular Straight Wall Opening
2 x Basic Wall:BERSnl_22_WA_kalkzandsteen150:1452579 | 01 eerste verdieping | 22.21 binnenwanden; constructief, massieve wanden (Uniformat) | BERSnl_22_WA_kalkzandsteen150 | Walls: Rectangular Straight Wall Opening
2 x Basic Wall:BERSnl_22_WA_kalkzandsteen150:1452696 | 01 eerste verdieping | 22.21 binnenwanden; constructief, massieve wanden (Uniformat) | BERSnl_22_WA_kalkzandsteen150 | Walls: Rectangular Straight Wall Opening
3 x Basic Wall:BERSnl_22_WA_kalkzandsteen214:1460420 | -00 fundatie | 22.21 binnenwanden; constructief, massieve wanden (Uniformat) | BERSnl_22_WA_kalkzandsteen214 | Walls: Rectangular Straight Wall Opening

# IfcPile: BERSnl_17_SFO_TLB_funderingspaal rond_gen_ISR:funderinspaal rond gen d 450 (93)
In: -00 fundatie
Classification: 17.0 paalfunderingen; algemeen (Uniformat)
Pset_PrecastConcreteElementGeneral - ElementWeight: 0 kg
Pset_ProductRequirements - Category: Structural Foundations
Pset_QuantityTakeOff - Reference: funderinspaal rond gen d 450
Name (BERSnl_17_SFO_TLB_funderingspaal rond_gen_ISR:funderinspaal rond gen d 450:...)
1465268
1479462
1479475
1479486
1479497
1479508
1479728
1479779
1480036
1480398
1480409
1480592
1480594
1480607
1480609
1480624
1480626
1480783
1481057
1481354
1481356
1481559
1481561
1481717
1481867
1482151
1482153
1482355
1482357
1482414
1482636
1482702
1482980
1483333
1483348
1483367
1483883
1483979
1484273
1484495
1484691
1484817
1485056
1485073
1485086
1485097
1485185
1485383
1485478
1485480
1485482
1485530
1485647
1485691
1485850
1486077
1486088
1486611
1486613
1486615
1486617
1486664
1486903
1486918
1487365
1487454
1487465
1488260
1488564
1488729
1488858
1489715
1490028
1490041
1490221
1490432
1490664
1490934
1491149
1491418
1491433
1491969
1492617
1492851
1493091
1493377
1505433
1505445
1506000
1506013
1506114
1506839
1507541

# IfcPile: BERSnl_17_SFO_TLB_funderingspaal rond_gen_ISR:funderinspaal rond gen d 450-1, BERSnl_17_SFO_TLB_funderingspaal rond_gen_ISR:funderinspaal rond gen d 450-1:1487694
In: -00 fundatie
Classification: 17.0 paalfunderingen; algemeen (Uniformat)
Pset_PrecastConcreteElementGeneral - ElementWeight: 0 kg
Pset_ProductRequirements - Category: Structural Foundations
Pset_QuantityTakeOff - Reference: funderinspaal rond gen d 450-1

# IfcPile: BERSnl_17_SFO_TLB_funderingspaal rond_gen_ISR:funderinspaal rond gen d 450-2, BERSnl_17_SFO_TLB_funderingspaal rond_gen_ISR:funderinspaal rond gen d 450-2:1489082
In: -00 fundatie
Classification: 17.0 paalfunderingen; algemeen (Uniformat)
Pset_PrecastConcreteElementGeneral - ElementWeight: 0 kg
Pset_ProductRequirements - Category: Structural Foundations
Pset_QuantityTakeOff - Reference: funderinspaal rond gen d 450-2

# IfcPile: BERSnl_17_SFO_TLB_funderingspaal rond_gen_ISR:funderinspaal rond gen d 450-3 (25)
In: -00 fundatie
Classification: 17.0 paalfunderingen; algemeen (Uniformat)
Pset_PrecastConcreteElementGeneral - ElementWeight: 0 kg
Pset_ProductRequirements - Category: Structural Foundations
Pset_QuantityTakeOff - Reference: funderinspaal rond gen d 450-3
Name (BERSnl_17_SFO_TLB_funderingspaal rond_gen_ISR:funderinspaal rond gen d 450-3:...)
1494590
1495416
1495431
1495446
1495588
1495827
1496250
1496827
1497122
1497124
1497143
1497145
1497228
1497491
1498418
1498503
1498516
1498529
1498542
1498553
1498883
1499159
1499642
1499655
1499711

# IfcReinforcingBar: Rebar Bar:SR_ø10 1 (8)
NominalDiameter: 10 mm; CrossSectionArea: 0.0000785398 m2; Classification: 28 Hoofddraagconstructies (Uniformat)
Pset_ProductRequirements - Category: Structural Rebar
Pset_QuantityTakeOff - Reference: SR_ø10 1
Pset_ReinforcingBarBendingsISOCD3766Common - ISOCD3766ShapeCode: 00 3
Name (Rebar Bar:SR_ø10 1 : Shape 00 3:...) | In | BarLength (mm) = ISOCD3766ShapeParameter_a (mm)
1118625: 1 | 01 eerste verdieping | 1463.34
1129958: 1 | 01 eerste verdieping | 1304.69
1135892: 1 | 01 eerste verdieping | 545.078
1142825: 1 | 01 eerste verdieping | 1099.8
1149207: 1 | 02 tweede verdieping | 1232.17
1190346: 1 | 02 tweede verdieping | 1293.86
1194198: 1 | 02 tweede verdieping | 1323.14
1300057: 1 | 01 eerste verdieping | 1074.66

# IfcReinforcingBar: Rebar Bar:SR_ø8 (30)
NominalDiameter: 8 mm; CrossSectionArea: 0.0000502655 m2; Classification: 28 Hoofddraagconstructies (Uniformat); Group: Rebar Bar:SR_ø8
Pset_ProductRequirements - Category: Structural Rebar
Pset_QuantityTakeOff - Reference: SR_ø8
Pset_ReinforcingBarBendingsISOCD3766Common - ISOCD3766ShapeCode: Rebar Shape 5; ISOCD3766ShapeParameter_a: 100 mm; ISOCD3766BendingStartHook: 90 deg
Name (Rebar Bar:SR_ø8 : Shape Rebar Shape 5:...) | In | BarLength (mm) | ISOCD3766ShapeParameter_b (mm) | ISOCD3766ShapeParameter_c (mm) | ISOCD3766ShapeParameter_d (mm) | ISOCD3766ShapeParameter_e (mm)
1118626: 1 | 01 eerste verdieping | 2375.6 | 180.534 | 765.685 | 130 | 146.534
1118626: 2 | 01 eerste verdieping | 2375.6 | 180.534 | 765.685 | 130 | 146.534
1122296: 1 | 01 eerste verdieping | 2375.6 | 180.534 | 765.685 | 130 | 146.534
1122296: 2 | 01 eerste verdieping | 2375.6 | 180.534 | 765.685 | 130 | 146.534
1130025: 1 | 01 eerste verdieping | 2615.24 | 235.003 | 815.718 | 211.643 | 119.359
1130025: 2 | 01 eerste verdieping | 2615.24 | 235.003 | 815.718 | 211.643 | 119.359
1134317: 1 | 01 eerste verdieping | 1953.72 | 182.798 | 598.285 | 159.512 | 119.286
1134317: 2 | 01 eerste verdieping | 1953.72 | 182.798 | 598.285 | 159.512 | 119.286
1136234: 1 | 01 eerste verdieping | 1863.16 | 182.798 | 591.044 | 146.557 | 132.241
1136234: 2 | 01 eerste verdieping | 1863.16 | 182.798 | 591.044 | 146.557 | 132.241
1142826: 1 | 01 eerste verdieping | 1985.61 | 180.534 | 590.293 | 130 | 146.534
1142826: 2 | 01 eerste verdieping | 1985.61 | 180.534 | 590.293 | 130 | 146.534
1143549: 1 | 01 eerste verdieping | 1985.61 | 180.534 | 590.293 | 130 | 146.534
1143549: 2 | 01 eerste verdieping | 1985.61 | 180.534 | 590.293 | 130 | 146.534
1149208: 1 | 02 tweede verdieping | 2502.41 | 181.218 | 672.464 | 147.218 | 129.999
1149208: 2 | 02 tweede verdieping | 2502.41 | 181.218 | 672.464 | 147.218 | 129.999
1152254: 1 | 02 tweede verdieping | 2472.42 | 181.218 | 672.464 | 147.218 | 129.999
1152254: 2 | 02 tweede verdieping | 2472.42 | 181.218 | 672.464 | 147.218 | 129.999
1190347: 1 | 02 tweede verdieping | 2529.93 | 186.368 | 682.609 | 150.393 | 131.975
1190347: 2 | 02 tweede verdieping | 2529.93 | 186.368 | 682.609 | 150.393 | 131.975
1190980: 1 | 02 tweede verdieping | 1799.95 | 186.368 | 682.609 | 150.393 | 131.975
1190980: 2 | 02 tweede verdieping | 1799.95 | 186.368 | 682.609 | 150.393 | 131.975
1194199: 1 | 02 tweede verdieping | 2145.07 | 182.798 | 669.84 | 141.945 | 136.853
1194199: 2 | 02 tweede verdieping | 2145.07 | 182.798 | 669.84 | 141.945 | 136.853
1195117: 1 | 02 tweede verdieping | 2145.07 | 182.798 | 669.84 | 141.945 | 136.853
1195117: 2 | 02 tweede verdieping | 2145.07 | 182.798 | 669.84 | 141.945 | 136.853
1298891: 1 | 01 eerste verdieping | 1853.06 | 180.534 | 598.973 | 181.227 | 96.6936
1298891: 2 | 01 eerste verdieping | 1853.06 | 180.534 | 598.973 | 181.227 | 96.6936
1304748: 1 | 01 eerste verdieping | 1074.46 | 178.445 | 364.222 | 96.3909 | 178.055
1304748: 2 | 01 eerste verdieping | 1074.46 | 178.445 | 364.222 | 96.3909 | 178.055

# IfcSlab: Floor:BERSnl_23_FL_druklaag 60 (4)
Type - PredefinedType: FLOOR; Material: f2_beton ihwg 60 mm
Type - Pset_ElementShading - Roughness: 304.8 mm
Type - Pset_ProductRequirements - Category: Floors
Type - Pset_ReinforcementBarPitchOfSlab - Description: betonvloer 200mm ihwg
Type - Pset_SlabCommon - IsExternal: no; ThermalTransmittance: 17.4333 kg/K/s3
Classification: 23.20 vloeren; constructief, algemeen (verzamelniveau) (Uniformat)
Pset_QuantityTakeOff - Reference: BERSnl_23_FL_druklaag 60
Pset_ReinforcementBarPitchOfSlab - Reference: BERSnl_23_FL_druklaag 60
Pset_SlabCommon - LoadBearing: yes; PitchAngle: 0 deg; Reference: BERSnl_23_FL_druklaag 60
Name (Floor:BERSnl_23_FL_druklaag 60:...) | In
663024 | 01 eerste verdieping
764536 | 01 eerste verdieping
819917 | 02 tweede verdieping
894573 | 02 tweede verdieping

# IfcSlab: Floor:BERSnl_23_FL_gewapend beton 200_gen_ISR (7)
Type - PredefinedType: FLOOR; Material: f2_beton ihwg 200 mm
Type - Pset_ElementShading - Roughness: 304.8 mm
Type - Pset_ProductRequirements - Category: Floors
Type - Pset_ReinforcementBarPitchOfSlab - Description: betonvloer 200mm ihwg
Type - Pset_SlabCommon - IsExternal: no; ThermalTransmittance: 5.23 kg/K/s3
Classification: 23.20 vloeren; constructief, algemeen (verzamelniveau) (Uniformat)
Pset_QuantityTakeOff - Reference: BERSnl_23_FL_gewapend beton 200_gen_ISR
Pset_ReinforcementBarPitchOfSlab - Reference: BERSnl_23_FL_gewapend beton 200_gen_ISR
Pset_SlabCommon - LoadBearing: yes; PitchAngle: 0 deg; Reference: BERSnl_23_FL_gewapend beton 200_gen_ISR
Name (Floor:BERSnl_23_FL_gewapend beton 200_gen_ISR:...) | In
732245 | 01 eerste verdieping
740645 | 01 eerste verdieping
746185 | 01 eerste verdieping
749007 | 01 eerste verdieping
872136 | 02 tweede verdieping
909975 | 02 tweede verdieping
923430 | 02 tweede verdieping

# IfcSlab: Floor:BERSnl_23_FL_gewapend beton 250_gen_ISR (2)
In: -00 fundatie
Type - PredefinedType: FLOOR; Material: f2_beton ihwg 250 mm
Type - Pset_ElementShading - Roughness: 304.8 mm
Type - Pset_ProductRequirements - Category: Floors
Type - Pset_ReinforcementBarPitchOfSlab - Description: betonvloer 250mm ihwg
Type - Pset_SlabCommon - IsExternal: no; ThermalTransmittance: 4.184 kg/K/s3
Classification: 23.20 vloeren; constructief, algemeen (verzamelniveau) (Uniformat)
Pset_QuantityTakeOff - Reference: BERSnl_23_FL_gewapend beton 250_gen_ISR
Pset_ReinforcementBarPitchOfSlab - Reference: BERSnl_23_FL_gewapend beton 250_gen_ISR
Pset_SlabCommon - LoadBearing: yes; PitchAngle: 0 deg; Reference: BERSnl_23_FL_gewapend beton 250_gen_ISR
Name (Floor:BERSnl_23_FL_gewapend beton 250_gen_ISR:...)
560555
563303

# IfcSlab: Floor:BERSnl_23_FL_isolatie 100_gen_ISR (3)
In: -00 fundatie
Type - PredefinedType: FLOOR; Material: n7_isolatie 100 mm
Type - Pset_ElementShading - Roughness: 304.8 mm
Type - Pset_ProductRequirements - Category: Floors
Type - Pset_ReinforcementBarPitchOfSlab - Description: isolatie 100mm
Type - Pset_SlabCommon - IsExternal: no
Classification: 23.10 vloeren; niet constructief, algemeen (verzamelniveau) (Uniformat)
Pset_QuantityTakeOff - Reference: BERSnl_23_FL_isolatie 100_gen_ISR
Pset_ReinforcementBarPitchOfSlab - Reference: BERSnl_23_FL_isolatie 100_gen_ISR
Pset_SlabCommon - PitchAngle: 0 deg; Reference: BERSnl_23_FL_isolatie 100_gen_ISR; LoadBearing: no
Name (Floor:BERSnl_23_FL_isolatie 100_gen_ISR:...)
508432
508456
508483

# IfcSlab: Floor:BERSnl_23_FL_kanaalplaatvloer 200_gen_ISR (21)
Type - PredefinedType: FLOOR; Material: f2_beton prefab 200 mm
Type - Pset_ElementShading - Roughness: 304.8 mm
Type - Pset_ProductRequirements - Category: Floors
Type - Pset_ReinforcementBarPitchOfSlab - Description: kanaalplaatvloer 200mm
Type - Pset_SlabCommon - IsExternal: no; ThermalTransmittance: 5.23 kg/K/s3
Classification: 23.20 vloeren; constructief, algemeen (verzamelniveau) (Uniformat)
Pset_QuantityTakeOff - Reference: BERSnl_23_FL_kanaalplaatvloer 200_gen_ISR
Pset_ReinforcementBarPitchOfSlab - Reference: BERSnl_23_FL_kanaalplaatvloer 200_gen_ISR
Pset_SlabCommon - LoadBearing: yes; PitchAngle: 0 deg; Reference: BERSnl_23_FL_kanaalplaatvloer 200_gen_ISR
Name (Floor:BERSnl_23_FL_kanaalplaatvloer 200_gen_ISR:...) | In
657313 | 01 eerste verdieping
657389 | 01 eerste verdieping
707746 | 01 eerste verdieping
711476 | 01 eerste verdieping
715588 | 01 eerste verdieping
731021 | 01 eerste verdieping
751033 | 01 eerste verdieping
762969 | 01 eerste verdieping
795761 | 01 eerste verdieping
807793 | 01 eerste verdieping
819878 | 02 tweede verdieping
821992 | 02 tweede verdieping
832267 | 02 tweede verdieping
836920 | 02 tweede verdieping
866973 | 02 tweede verdieping
868368 | 02 tweede verdieping
872461 | 02 tweede verdieping
888757 | 02 tweede verdieping
904544 | 02 tweede verdieping
911819 | 02 tweede verdieping
913376 | 02 tweede verdieping

# IfcSlab: Floor:BERSnl_23_FL_kanaalplaatvloer 260_gen_ISR, Floor:BERSnl_23_FL_kanaalplaatvloer 260_gen_ISR:701354
In: 01 eerste verdieping
Type - PredefinedType: FLOOR; Material: f2_beton prefab 260 mm
Type - Pset_ElementShading - Roughness: 304.8 mm
Type - Pset_ProductRequirements - Category: Floors
Type - Pset_ReinforcementBarPitchOfSlab - Description: kanaalplaatvloer 260mm
Type - Pset_SlabCommon - IsExternal: no; ThermalTransmittance: 4.02308 kg/K/s3
Classification: 23.20 vloeren; constructief, algemeen (verzamelniveau) (Uniformat)
Pset_QuantityTakeOff - Reference: BERSnl_23_FL_kanaalplaatvloer 260_gen_ISR
Pset_ReinforcementBarPitchOfSlab - Reference: BERSnl_23_FL_kanaalplaatvloer 260_gen_ISR
Pset_SlabCommon - LoadBearing: yes; PitchAngle: 0 deg; Reference: BERSnl_23_FL_kanaalplaatvloer 260_gen_ISR

# IfcSlab: Floor:BERSnl_23_FL_kanaalplaatvloer 265 (18)
Type - PredefinedType: FLOOR; Material: f2_beton prefab 265 mm
Type - Pset_ElementShading - Roughness: 304.8 mm
Type - Pset_ProductRequirements - Category: Floors
Type - Pset_ReinforcementBarPitchOfSlab - Description: kanaalplaatvloer 260mm
Type - Pset_SlabCommon - IsExternal: no; ThermalTransmittance: 3.94717 kg/K/s3
Classification: 23.20 vloeren; constructief, algemeen (verzamelniveau) (Uniformat)
Pset_QuantityTakeOff - Reference: BERSnl_23_FL_kanaalplaatvloer 265
Pset_ReinforcementBarPitchOfSlab - Reference: BERSnl_23_FL_kanaalplaatvloer 265
Pset_SlabCommon - LoadBearing: yes; Reference: BERSnl_23_FL_kanaalplaatvloer 265; PitchAngle: 0 deg
Name (Floor:BERSnl_23_FL_kanaalplaatvloer 265:...) | In
508226 | -00 fundatie
516024 | -00 fundatie
520775 | -00 fundatie
532314 | -00 fundatie
541637 | -00 fundatie
547750 | -00 fundatie
554670 | -00 fundatie
587670 | -00 fundatie
597633 | 00 begane grond
602191 | -00 fundatie
608912 | -00 fundatie
618535 | -00 fundatie
620543 | -00 fundatie
627959 | -00 fundatie
630079 | 00 begane grond
642293 | 00 begane grond
647979 | -00 fundatie
653337 | -00 fundatie

# IfcSlab: Floor:BERSnl_23_FLprefab 200, Floor:BERSnl_23_FLprefab 200:690348
In: 01 eerste verdieping
Type - PredefinedType: FLOOR; Material: f2_beton ihwg 200 mm
Type - Pset_ElementShading - Roughness: 304.8 mm
Type - Pset_ProductRequirements - Category: Floors
Type - Pset_ReinforcementBarPitchOfSlab - Description: betonvloer 250mm ihwg
Type - Pset_SlabCommon - IsExternal: no; ThermalTransmittance: 5.23 kg/K/s3
Classification: 23.20 vloeren; constructief, algemeen (verzamelniveau) (Uniformat)
Pset_QuantityTakeOff - Reference: BERSnl_23_FLprefab 200
Pset_ReinforcementBarPitchOfSlab - Reference: BERSnl_23_FLprefab 200
Pset_SlabCommon - LoadBearing: yes; PitchAngle: 0 deg; Reference: BERSnl_23_FLprefab 200

# IfcSlab: Floor:BERSnl_27_FL_staal 75_gen_ISR (3)
Type - PredefinedType: ROOF; Material: h2_staal 75 mm
Type - Pset_ElementShading - Roughness: 304.8 mm
Type - Pset_ProductRequirements - Category: Floors
Type - Pset_ReinforcementBarPitchOfSlab - Description: stalen dakvloerconstructie 75mm
Type - Pset_SlabCommon - IsExternal: no; ThermalTransmittance: 600 kg/K/s3
Classification: 27.21 daken; constructief, vlakke daken (Uniformat)
Pset_QuantityTakeOff - Reference: BERSnl_27_FL_staal 75_gen_ISR
Pset_ReinforcementBarPitchOfSlab - Reference: BERSnl_27_FL_staal 75_gen_ISR
Pset_SlabCommon - LoadBearing: yes; Reference: BERSnl_27_FL_staal 75_gen_ISR
Name (Floor:BERSnl_27_FL_staal 75_gen_ISR:...) | In | PitchAngle (deg)
861440 | 03 derde verdieping | 0
969426 | 01 eerste verdieping | 0.908753
982029 | 01 eerste verdieping | 0.908753

# IfcSlab: Floor:NLRS_23_FL_isolatie 130 (18)
Type - PredefinedType: FLOOR; Material: 00_Isolatie_generiek 130 mm
Type - Pset_ElementShading - Roughness: 304.8 mm
Type - Pset_ProductRequirements - Category: Floors
Type - Pset_ReinforcementBarPitchOfSlab - Description: Isolatie 130mm
Type - Pset_SlabCommon - IsExternal: no
Classification: 23.10 vloeren; niet constructief, algemeen (verzamelniveau) (Uniformat)
Pset_QuantityTakeOff - Reference: NLRS_23_FL_isolatie 130
Pset_ReinforcementBarPitchOfSlab - Reference: NLRS_23_FL_isolatie 130
Pset_SlabCommon - LoadBearing: yes; PitchAngle: 0 deg; Reference: NLRS_23_FL_isolatie 130
Name (Floor:NLRS_23_FL_isolatie 130:...) | In
508830 | -00 fundatie
517437 | -00 fundatie
521074 | -00 fundatie
532632 | -00 fundatie
544210 | -00 fundatie
550140 | -00 fundatie
588908 | -00 fundatie
598765 | 00 begane grond
603394 | -00 fundatie
619742 | -00 fundatie
621952 | -00 fundatie
628957 | -00 fundatie
631657 | 00 begane grond
640527 | -00 fundatie
643888 | 00 begane grond
649355 | -00 fundatie
654037 | -00 fundatie
980897 | -00 fundatie

# IfcWall: Basic Wall:BERSnl_22_WA_kalkzandsteen214 (2)
In: -00 fundatie
Type - PredefinedType: STANDARD; Material: f1_kalkzandsteen 214 mm
Type - Pset_ElementShading - Roughness: 304.8 mm
Type - Pset_ProductRequirements - Category: Walls
Type - Pset_ReinforcementBarPitchOfWall - Description: Kalkzandsteen 214mm
Type - Pset_WallCommon - ThermalTransmittance: 13.5514 kg/K/s3; IsExternal: no
Classification: 22.21 binnenwanden; constructief, massieve wanden (Uniformat)
Pset_QuantityTakeOff - Reference: BERSnl_22_WA_kalkzandsteen214
Pset_ReinforcementBarPitchOfWall - Reference: BERSnl_22_WA_kalkzandsteen214
Pset_WallCommon - Reference: BERSnl_22_WA_kalkzandsteen214; ExtendToStructure: no; LoadBearing: yes
Name (Basic Wall:BERSnl_22_WA_kalkzandsteen214:...)
554535
558977

# IfcWallStandardCase: Basic Wall:BERSnl_21_WA_metselwerk 100_gen_ISR (7)
In: -00 fundatie
Type - PredefinedType: STANDARD; Material: g2_metselwerk bruin 100 mm
Type - Pset_ElementShading - Roughness: 304.8 mm
Type - Pset_ProductRequirements - Category: Walls
Type - Pset_ReinforcementBarPitchOfWall - Description: metselwerk 100mm
Type - Pset_WallCommon - IsExternal: yes; ThermalTransmittance: 5.4 kg/K/s3
Classification: 21.11 buitenwanden; niet constructief, massieve wanden (Uniformat)
Pset_QuantityTakeOff - Reference: BERSnl_21_WA_metselwerk 100_gen_ISR
Pset_ReinforcementBarPitchOfWall - Reference: BERSnl_21_WA_metselwerk 100_gen_ISR
Pset_WallCommon - ExtendToStructure: no; LoadBearing: yes; Reference: BERSnl_21_WA_metselwerk 100_gen_ISR
Name (Basic Wall:BERSnl_21_WA_metselwerk 100_gen_ISR:...)
615876
616135
625753
626674
651006
707183
978396

# IfcWallStandardCase: Basic Wall:BERSnl_22_WA_kalkzandsteen 100_gen_ISR (23)
In: -00 fundatie
Type - PredefinedType: STANDARD; Material: f1_kalkzandsteen 100 mm
Type - Pset_ElementShading - Roughness: 304.8 mm
Type - Pset_ProductRequirements - Category: Walls
Type - Pset_ReinforcementBarPitchOfWall - Description: kalkzandsteen 100mm
Type - Pset_WallCommon - IsExternal: no; ThermalTransmittance: 29 kg/K/s3
Classification: 22.21 binnenwanden; constructief, massieve wanden (Uniformat)
Pset_QuantityTakeOff - Reference: BERSnl_22_WA_kalkzandsteen 100_gen_ISR
Pset_ReinforcementBarPitchOfWall - Reference: BERSnl_22_WA_kalkzandsteen 100_gen_ISR
Pset_WallCommon - ExtendToStructure: no; LoadBearing: yes; Reference: BERSnl_22_WA_kalkzandsteen 100_gen_ISR
Name (Basic Wall:BERSnl_22_WA_kalkzandsteen 100_gen_ISR:...)
525450
528432
532243
532747
533151
534061
535483
536169
537911
538351
539658
540920
547484
1048131
1057887
1062862
1067051
1068349
1068467
1154397
1207897
1209942
1222365

# IfcWallStandardCase: Basic Wall:BERSnl_22_WA_kalkzandsteen 120_gen_ISR (6)
In: -00 fundatie
Type - PredefinedType: STANDARD; Material: f1_kalkzandsteen 120 mm
Type - Pset_ElementShading - Roughness: 304.8 mm
Type - Pset_ProductRequirements - Category: Walls
Type - Pset_ReinforcementBarPitchOfWall - Description: kalkzandsteen 120mm
Type - Pset_WallCommon - IsExternal: no; ThermalTransmittance: 24.1667 kg/K/s3
Classification: 22.21 binnenwanden; constructief, massieve wanden (Uniformat)
Pset_QuantityTakeOff - Reference: BERSnl_22_WA_kalkzandsteen 120_gen_ISR
Pset_ReinforcementBarPitchOfWall - Reference: BERSnl_22_WA_kalkzandsteen 120_gen_ISR
Pset_WallCommon - ExtendToStructure: no; LoadBearing: yes; Reference: BERSnl_22_WA_kalkzandsteen 120_gen_ISR
Name (Basic Wall:BERSnl_22_WA_kalkzandsteen 120_gen_ISR:...)
521499
521991
523596
523989
524644
531474

# IfcWallStandardCase: Basic Wall:BERSnl_22_WA_kalkzandsteen150 (34)
Type - PredefinedType: STANDARD; Material: f1_kalkzandsteen 150 mm
Type - Pset_ElementShading - Roughness: 304.8 mm
Type - Pset_ProductRequirements - Category: Walls
Type - Pset_ReinforcementBarPitchOfWall - Description: Kalkzandsteen 214mm
Type - Pset_WallCommon - IsExternal: no; ThermalTransmittance: 19.3333 kg/K/s3
Classification: 22.21 binnenwanden; constructief, massieve wanden (Uniformat)
Pset_QuantityTakeOff - Reference: BERSnl_22_WA_kalkzandsteen150
Pset_ReinforcementBarPitchOfWall - Reference: BERSnl_22_WA_kalkzandsteen150
Pset_WallCommon - ExtendToStructure: no; LoadBearing: yes; Reference: BERSnl_22_WA_kalkzandsteen150
Name (Basic Wall:BERSnl_22_WA_kalkzandsteen150:...) | In
500333 | -00 fundatie
508973 | -00 fundatie
523399 | -00 fundatie
524999 | -00 fundatie
553225 | -00 fundatie
557927 | -00 fundatie
576330 | 00 begane grond
578548 | -00 fundatie
593741 | 00 begane grond
614263 | -00 fundatie
615192 | -00 fundatie
625124 | -00 fundatie
627351 | -00 fundatie
638856 | 00 begane grond
642004 | 00 begane grond
667331 | 01 eerste verdieping
667943 | 01 eerste verdieping
668638 | 01 eerste verdieping
686158 | 01 eerste verdieping
711769 | 01 eerste verdieping
712043 | 01 eerste verdieping
736952 | -00 fundatie
764030 | 01 eerste verdieping
765305 | 01 eerste verdieping
865783 | 01 eerste verdieping
868693 | 01 eerste verdieping
874377 | 02 tweede verdieping
987020 | 00 begane grond
1388924 | -00 fundatie
1391724 | -00 fundatie
1391918 | -00 fundatie
1452254 | 01 eerste verdieping
1452579 | 01 eerste verdieping
1452696 | 01 eerste verdieping

# IfcWallStandardCase: Basic Wall:BERSnl_22_WA_kalkzandsteen214 (14)
Type - PredefinedType: STANDARD; Material: f1_kalkzandsteen 214 mm
Type - Pset_ElementShading - Roughness: 304.8 mm
Type - Pset_ProductRequirements - Category: Walls
Type - Pset_ReinforcementBarPitchOfWall - Description: Kalkzandsteen 214mm
Type - Pset_WallCommon - ThermalTransmittance: 13.5514 kg/K/s3; IsExternal: no
Classification: 22.21 binnenwanden; constructief, massieve wanden (Uniformat)
Pset_QuantityTakeOff - Reference: BERSnl_22_WA_kalkzandsteen214
Pset_ReinforcementBarPitchOfWall - Reference: BERSnl_22_WA_kalkzandsteen214
Pset_WallCommon - Reference: BERSnl_22_WA_kalkzandsteen214; ExtendToStructure: no; LoadBearing: yes
Name (Basic Wall:BERSnl_22_WA_kalkzandsteen214:...) | In
500331 | -00 fundatie
571963 | 00 begane grond
638965 | 00 begane grond
641551 | 00 begane grond
676283 | 01 eerste verdieping
817353 | 01 eerste verdieping
818536 | 01 eerste verdieping
819006 | 01 eerste verdieping
912669 | 01 eerste verdieping
1227086 | -00 fundatie
1227388 | -00 fundatie
1229615 | 02 tweede verdieping
1246842 | -00 fundatie
1460420 | -00 fundatie
